VERSION 5.8 ;
BUSBITCHARS "[]" ;
DIVIDERCHAR "/" ;
UNITS
    DATABASE MICRONS 1000 ;
END UNITS

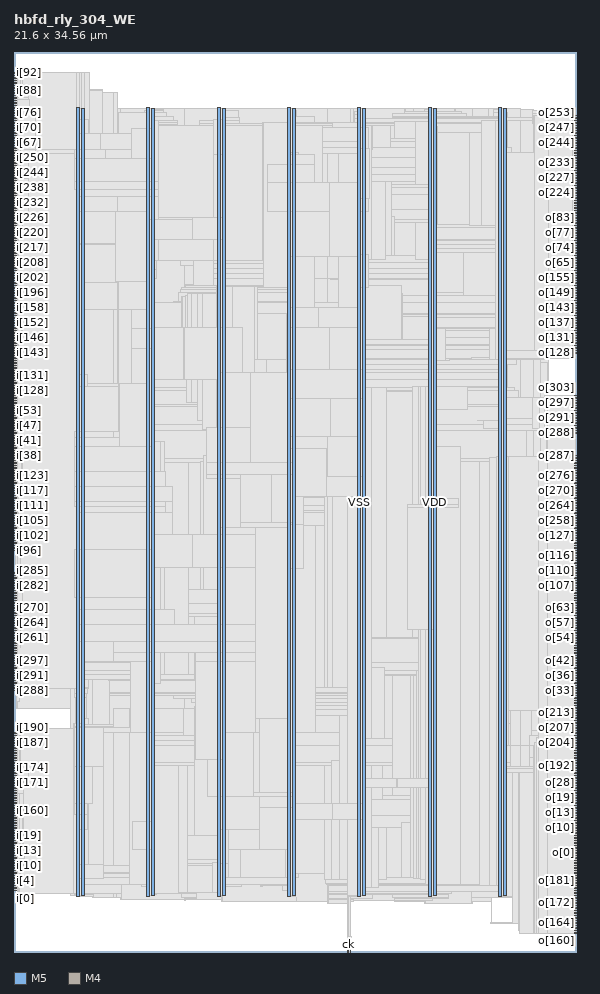
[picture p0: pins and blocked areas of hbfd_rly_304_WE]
MACRO hbfd_rly_304_WE
  FOREIGN hbfd_rly_304_WE 0 0 ;
  CLASS BLOCK ;
  SIZE 21.6 BY 34.56 ;
  PIN ck
    DIRECTION INPUT ;
    USE SIGNAL ;
    PORT
      LAYER M5 ;
        RECT  12.816 0 12.84 0.084 ;
    END
  END ck
  PIN i[0]
    DIRECTION INPUT ;
    USE SIGNAL ;
    PORT
      LAYER M4 ;
        RECT  0 2.352 0.084 2.376 ;
    END
  END i[0]
  PIN i[100]
    DIRECTION INPUT ;
    USE SIGNAL ;
    PORT
      LAYER M4 ;
        RECT  0 15.792 0.084 15.816 ;
    END
  END i[100]
  PIN i[101]
    DIRECTION INPUT ;
    USE SIGNAL ;
    PORT
      LAYER M4 ;
        RECT  0 15.888 0.084 15.912 ;
    END
  END i[101]
  PIN i[102]
    DIRECTION INPUT ;
    USE SIGNAL ;
    PORT
      LAYER M4 ;
        RECT  0 15.984 0.084 16.008 ;
    END
  END i[102]
  PIN i[103]
    DIRECTION INPUT ;
    USE SIGNAL ;
    PORT
      LAYER M4 ;
        RECT  0 16.08 0.084 16.104 ;
    END
  END i[103]
  PIN i[104]
    DIRECTION INPUT ;
    USE SIGNAL ;
    PORT
      LAYER M4 ;
        RECT  0 16.176 0.084 16.2 ;
    END
  END i[104]
  PIN i[105]
    DIRECTION INPUT ;
    USE SIGNAL ;
    PORT
      LAYER M4 ;
        RECT  0 16.272 0.084 16.296 ;
    END
  END i[105]
  PIN i[106]
    DIRECTION INPUT ;
    USE SIGNAL ;
    PORT
      LAYER M4 ;
        RECT  0 16.368 0.084 16.392 ;
    END
  END i[106]
  PIN i[107]
    DIRECTION INPUT ;
    USE SIGNAL ;
    PORT
      LAYER M4 ;
        RECT  0 16.464 0.084 16.488 ;
    END
  END i[107]
  PIN i[108]
    DIRECTION INPUT ;
    USE SIGNAL ;
    PORT
      LAYER M4 ;
        RECT  0 16.56 0.084 16.584 ;
    END
  END i[108]
  PIN i[109]
    DIRECTION INPUT ;
    USE SIGNAL ;
    PORT
      LAYER M4 ;
        RECT  0 16.656 0.084 16.68 ;
    END
  END i[109]
  PIN i[10]
    DIRECTION INPUT ;
    USE SIGNAL ;
    PORT
      LAYER M4 ;
        RECT  0 3.312 0.084 3.336 ;
    END
  END i[10]
  PIN i[110]
    DIRECTION INPUT ;
    USE SIGNAL ;
    PORT
      LAYER M4 ;
        RECT  0 16.752 0.084 16.776 ;
    END
  END i[110]
  PIN i[111]
    DIRECTION INPUT ;
    USE SIGNAL ;
    PORT
      LAYER M4 ;
        RECT  0 16.848 0.084 16.872 ;
    END
  END i[111]
  PIN i[112]
    DIRECTION INPUT ;
    USE SIGNAL ;
    PORT
      LAYER M4 ;
        RECT  0 16.944 0.084 16.968 ;
    END
  END i[112]
  PIN i[113]
    DIRECTION INPUT ;
    USE SIGNAL ;
    PORT
      LAYER M4 ;
        RECT  0 17.04 0.084 17.064 ;
    END
  END i[113]
  PIN i[114]
    DIRECTION INPUT ;
    USE SIGNAL ;
    PORT
      LAYER M4 ;
        RECT  0 17.136 0.084 17.16 ;
    END
  END i[114]
  PIN i[115]
    DIRECTION INPUT ;
    USE SIGNAL ;
    PORT
      LAYER M4 ;
        RECT  0 17.232 0.084 17.256 ;
    END
  END i[115]
  PIN i[116]
    DIRECTION INPUT ;
    USE SIGNAL ;
    PORT
      LAYER M4 ;
        RECT  0 17.328 0.084 17.352 ;
    END
  END i[116]
  PIN i[117]
    DIRECTION INPUT ;
    USE SIGNAL ;
    PORT
      LAYER M4 ;
        RECT  0 17.424 0.084 17.448 ;
    END
  END i[117]
  PIN i[118]
    DIRECTION INPUT ;
    USE SIGNAL ;
    PORT
      LAYER M4 ;
        RECT  0 17.52 0.084 17.544 ;
    END
  END i[118]
  PIN i[119]
    DIRECTION INPUT ;
    USE SIGNAL ;
    PORT
      LAYER M4 ;
        RECT  0 17.616 0.084 17.64 ;
    END
  END i[119]
  PIN i[11]
    DIRECTION INPUT ;
    USE SIGNAL ;
    PORT
      LAYER M4 ;
        RECT  0 3.408 0.084 3.432 ;
    END
  END i[11]
  PIN i[120]
    DIRECTION INPUT ;
    USE SIGNAL ;
    PORT
      LAYER M4 ;
        RECT  0 17.712 0.084 17.736 ;
    END
  END i[120]
  PIN i[121]
    DIRECTION INPUT ;
    USE SIGNAL ;
    PORT
      LAYER M4 ;
        RECT  0 17.808 0.084 17.832 ;
    END
  END i[121]
  PIN i[122]
    DIRECTION INPUT ;
    USE SIGNAL ;
    PORT
      LAYER M4 ;
        RECT  0 17.904 0.084 17.928 ;
    END
  END i[122]
  PIN i[123]
    DIRECTION INPUT ;
    USE SIGNAL ;
    PORT
      LAYER M4 ;
        RECT  0 18 0.084 18.024 ;
    END
  END i[123]
  PIN i[124]
    DIRECTION INPUT ;
    USE SIGNAL ;
    PORT
      LAYER M4 ;
        RECT  0 18.096 0.084 18.12 ;
    END
  END i[124]
  PIN i[125]
    DIRECTION INPUT ;
    USE SIGNAL ;
    PORT
      LAYER M4 ;
        RECT  0 18.192 0.084 18.216 ;
    END
  END i[125]
  PIN i[126]
    DIRECTION INPUT ;
    USE SIGNAL ;
    PORT
      LAYER M4 ;
        RECT  0 18.288 0.084 18.312 ;
    END
  END i[126]
  PIN i[127]
    DIRECTION INPUT ;
    USE SIGNAL ;
    PORT
      LAYER M4 ;
        RECT  0 18.384 0.084 18.408 ;
    END
  END i[127]
  PIN i[128]
    DIRECTION INPUT ;
    USE SIGNAL ;
    PORT
      LAYER M4 ;
        RECT  0 21.552 0.084 21.576 ;
    END
  END i[128]
  PIN i[129]
    DIRECTION INPUT ;
    USE SIGNAL ;
    PORT
      LAYER M4 ;
        RECT  0 21.648 0.084 21.672 ;
    END
  END i[129]
  PIN i[12]
    DIRECTION INPUT ;
    USE SIGNAL ;
    PORT
      LAYER M4 ;
        RECT  0 3.504 0.084 3.528 ;
    END
  END i[12]
  PIN i[130]
    DIRECTION INPUT ;
    USE SIGNAL ;
    PORT
      LAYER M4 ;
        RECT  0 21.744 0.084 21.768 ;
    END
  END i[130]
  PIN i[131]
    DIRECTION INPUT ;
    USE SIGNAL ;
    PORT
      LAYER M4 ;
        RECT  0 21.84 0.084 21.864 ;
    END
  END i[131]
  PIN i[132]
    DIRECTION INPUT ;
    USE SIGNAL ;
    PORT
      LAYER M4 ;
        RECT  0 21.936 0.084 21.96 ;
    END
  END i[132]
  PIN i[133]
    DIRECTION INPUT ;
    USE SIGNAL ;
    PORT
      LAYER M4 ;
        RECT  0 22.032 0.084 22.056 ;
    END
  END i[133]
  PIN i[134]
    DIRECTION INPUT ;
    USE SIGNAL ;
    PORT
      LAYER M4 ;
        RECT  0 22.128 0.084 22.152 ;
    END
  END i[134]
  PIN i[135]
    DIRECTION INPUT ;
    USE SIGNAL ;
    PORT
      LAYER M4 ;
        RECT  0 22.224 0.084 22.248 ;
    END
  END i[135]
  PIN i[136]
    DIRECTION INPUT ;
    USE SIGNAL ;
    PORT
      LAYER M4 ;
        RECT  0 22.32 0.084 22.344 ;
    END
  END i[136]
  PIN i[137]
    DIRECTION INPUT ;
    USE SIGNAL ;
    PORT
      LAYER M4 ;
        RECT  0 22.416 0.084 22.44 ;
    END
  END i[137]
  PIN i[138]
    DIRECTION INPUT ;
    USE SIGNAL ;
    PORT
      LAYER M4 ;
        RECT  0 22.512 0.084 22.536 ;
    END
  END i[138]
  PIN i[139]
    DIRECTION INPUT ;
    USE SIGNAL ;
    PORT
      LAYER M4 ;
        RECT  0 22.608 0.084 22.632 ;
    END
  END i[139]
  PIN i[13]
    DIRECTION INPUT ;
    USE SIGNAL ;
    PORT
      LAYER M4 ;
        RECT  0 3.6 0.084 3.624 ;
    END
  END i[13]
  PIN i[140]
    DIRECTION INPUT ;
    USE SIGNAL ;
    PORT
      LAYER M4 ;
        RECT  0 22.704 0.084 22.728 ;
    END
  END i[140]
  PIN i[141]
    DIRECTION INPUT ;
    USE SIGNAL ;
    PORT
      LAYER M4 ;
        RECT  0 22.8 0.084 22.824 ;
    END
  END i[141]
  PIN i[142]
    DIRECTION INPUT ;
    USE SIGNAL ;
    PORT
      LAYER M4 ;
        RECT  0 22.896 0.084 22.92 ;
    END
  END i[142]
  PIN i[143]
    DIRECTION INPUT ;
    USE SIGNAL ;
    PORT
      LAYER M4 ;
        RECT  0 22.992 0.084 23.016 ;
    END
  END i[143]
  PIN i[144]
    DIRECTION INPUT ;
    USE SIGNAL ;
    PORT
      LAYER M4 ;
        RECT  0 23.088 0.084 23.112 ;
    END
  END i[144]
  PIN i[145]
    DIRECTION INPUT ;
    USE SIGNAL ;
    PORT
      LAYER M4 ;
        RECT  0 23.184 0.084 23.208 ;
    END
  END i[145]
  PIN i[146]
    DIRECTION INPUT ;
    USE SIGNAL ;
    PORT
      LAYER M4 ;
        RECT  0 23.28 0.084 23.304 ;
    END
  END i[146]
  PIN i[147]
    DIRECTION INPUT ;
    USE SIGNAL ;
    PORT
      LAYER M4 ;
        RECT  0 23.376 0.084 23.4 ;
    END
  END i[147]
  PIN i[148]
    DIRECTION INPUT ;
    USE SIGNAL ;
    PORT
      LAYER M4 ;
        RECT  0 23.472 0.084 23.496 ;
    END
  END i[148]
  PIN i[149]
    DIRECTION INPUT ;
    USE SIGNAL ;
    PORT
      LAYER M4 ;
        RECT  0 23.568 0.084 23.592 ;
    END
  END i[149]
  PIN i[14]
    DIRECTION INPUT ;
    USE SIGNAL ;
    PORT
      LAYER M4 ;
        RECT  0 3.696 0.084 3.72 ;
    END
  END i[14]
  PIN i[150]
    DIRECTION INPUT ;
    USE SIGNAL ;
    PORT
      LAYER M4 ;
        RECT  0 23.664 0.084 23.688 ;
    END
  END i[150]
  PIN i[151]
    DIRECTION INPUT ;
    USE SIGNAL ;
    PORT
      LAYER M4 ;
        RECT  0 23.76 0.084 23.784 ;
    END
  END i[151]
  PIN i[152]
    DIRECTION INPUT ;
    USE SIGNAL ;
    PORT
      LAYER M4 ;
        RECT  0 23.856 0.084 23.88 ;
    END
  END i[152]
  PIN i[153]
    DIRECTION INPUT ;
    USE SIGNAL ;
    PORT
      LAYER M4 ;
        RECT  0 23.952 0.084 23.976 ;
    END
  END i[153]
  PIN i[154]
    DIRECTION INPUT ;
    USE SIGNAL ;
    PORT
      LAYER M4 ;
        RECT  0 24.048 0.084 24.072 ;
    END
  END i[154]
  PIN i[155]
    DIRECTION INPUT ;
    USE SIGNAL ;
    PORT
      LAYER M4 ;
        RECT  0 24.144 0.084 24.168 ;
    END
  END i[155]
  PIN i[156]
    DIRECTION INPUT ;
    USE SIGNAL ;
    PORT
      LAYER M4 ;
        RECT  0 24.24 0.084 24.264 ;
    END
  END i[156]
  PIN i[157]
    DIRECTION INPUT ;
    USE SIGNAL ;
    PORT
      LAYER M4 ;
        RECT  0 24.336 0.084 24.36 ;
    END
  END i[157]
  PIN i[158]
    DIRECTION INPUT ;
    USE SIGNAL ;
    PORT
      LAYER M4 ;
        RECT  0 24.432 0.084 24.456 ;
    END
  END i[158]
  PIN i[159]
    DIRECTION INPUT ;
    USE SIGNAL ;
    PORT
      LAYER M4 ;
        RECT  0 24.528 0.084 24.552 ;
    END
  END i[159]
  PIN i[15]
    DIRECTION INPUT ;
    USE SIGNAL ;
    PORT
      LAYER M4 ;
        RECT  0 3.792 0.084 3.816 ;
    END
  END i[15]
  PIN i[160]
    DIRECTION INPUT ;
    USE SIGNAL ;
    PORT
      LAYER M4 ;
        RECT  0 5.424 0.084 5.448 ;
    END
  END i[160]
  PIN i[161]
    DIRECTION INPUT ;
    USE SIGNAL ;
    PORT
      LAYER M4 ;
        RECT  0 5.52 0.084 5.544 ;
    END
  END i[161]
  PIN i[162]
    DIRECTION INPUT ;
    USE SIGNAL ;
    PORT
      LAYER M4 ;
        RECT  0 5.616 0.084 5.64 ;
    END
  END i[162]
  PIN i[163]
    DIRECTION INPUT ;
    USE SIGNAL ;
    PORT
      LAYER M4 ;
        RECT  0 5.712 0.084 5.736 ;
    END
  END i[163]
  PIN i[164]
    DIRECTION INPUT ;
    USE SIGNAL ;
    PORT
      LAYER M4 ;
        RECT  0 5.808 0.084 5.832 ;
    END
  END i[164]
  PIN i[165]
    DIRECTION INPUT ;
    USE SIGNAL ;
    PORT
      LAYER M4 ;
        RECT  0 5.904 0.084 5.928 ;
    END
  END i[165]
  PIN i[166]
    DIRECTION INPUT ;
    USE SIGNAL ;
    PORT
      LAYER M4 ;
        RECT  0 6 0.084 6.024 ;
    END
  END i[166]
  PIN i[167]
    DIRECTION INPUT ;
    USE SIGNAL ;
    PORT
      LAYER M4 ;
        RECT  0 6.096 0.084 6.12 ;
    END
  END i[167]
  PIN i[168]
    DIRECTION INPUT ;
    USE SIGNAL ;
    PORT
      LAYER M4 ;
        RECT  0 6.192 0.084 6.216 ;
    END
  END i[168]
  PIN i[169]
    DIRECTION INPUT ;
    USE SIGNAL ;
    PORT
      LAYER M4 ;
        RECT  0 6.288 0.084 6.312 ;
    END
  END i[169]
  PIN i[16]
    DIRECTION INPUT ;
    USE SIGNAL ;
    PORT
      LAYER M4 ;
        RECT  0 3.888 0.084 3.912 ;
    END
  END i[16]
  PIN i[170]
    DIRECTION INPUT ;
    USE SIGNAL ;
    PORT
      LAYER M4 ;
        RECT  0 6.384 0.084 6.408 ;
    END
  END i[170]
  PIN i[171]
    DIRECTION INPUT ;
    USE SIGNAL ;
    PORT
      LAYER M4 ;
        RECT  0 6.48 0.084 6.504 ;
    END
  END i[171]
  PIN i[172]
    DIRECTION INPUT ;
    USE SIGNAL ;
    PORT
      LAYER M4 ;
        RECT  0 6.576 0.084 6.6 ;
    END
  END i[172]
  PIN i[173]
    DIRECTION INPUT ;
    USE SIGNAL ;
    PORT
      LAYER M4 ;
        RECT  0 6.672 0.084 6.696 ;
    END
  END i[173]
  PIN i[174]
    DIRECTION INPUT ;
    USE SIGNAL ;
    PORT
      LAYER M4 ;
        RECT  0 6.768 0.084 6.792 ;
    END
  END i[174]
  PIN i[175]
    DIRECTION INPUT ;
    USE SIGNAL ;
    PORT
      LAYER M4 ;
        RECT  0 6.864 0.084 6.888 ;
    END
  END i[175]
  PIN i[176]
    DIRECTION INPUT ;
    USE SIGNAL ;
    PORT
      LAYER M4 ;
        RECT  0 6.96 0.084 6.984 ;
    END
  END i[176]
  PIN i[177]
    DIRECTION INPUT ;
    USE SIGNAL ;
    PORT
      LAYER M4 ;
        RECT  0 7.056 0.084 7.08 ;
    END
  END i[177]
  PIN i[178]
    DIRECTION INPUT ;
    USE SIGNAL ;
    PORT
      LAYER M4 ;
        RECT  0 7.152 0.084 7.176 ;
    END
  END i[178]
  PIN i[179]
    DIRECTION INPUT ;
    USE SIGNAL ;
    PORT
      LAYER M4 ;
        RECT  0 7.248 0.084 7.272 ;
    END
  END i[179]
  PIN i[17]
    DIRECTION INPUT ;
    USE SIGNAL ;
    PORT
      LAYER M4 ;
        RECT  0 3.984 0.084 4.008 ;
    END
  END i[17]
  PIN i[180]
    DIRECTION INPUT ;
    USE SIGNAL ;
    PORT
      LAYER M4 ;
        RECT  0 7.344 0.084 7.368 ;
    END
  END i[180]
  PIN i[181]
    DIRECTION INPUT ;
    USE SIGNAL ;
    PORT
      LAYER M4 ;
        RECT  0 7.44 0.084 7.464 ;
    END
  END i[181]
  PIN i[182]
    DIRECTION INPUT ;
    USE SIGNAL ;
    PORT
      LAYER M4 ;
        RECT  0 7.536 0.084 7.56 ;
    END
  END i[182]
  PIN i[183]
    DIRECTION INPUT ;
    USE SIGNAL ;
    PORT
      LAYER M4 ;
        RECT  0 7.632 0.084 7.656 ;
    END
  END i[183]
  PIN i[184]
    DIRECTION INPUT ;
    USE SIGNAL ;
    PORT
      LAYER M4 ;
        RECT  0 7.728 0.084 7.752 ;
    END
  END i[184]
  PIN i[185]
    DIRECTION INPUT ;
    USE SIGNAL ;
    PORT
      LAYER M4 ;
        RECT  0 7.824 0.084 7.848 ;
    END
  END i[185]
  PIN i[186]
    DIRECTION INPUT ;
    USE SIGNAL ;
    PORT
      LAYER M4 ;
        RECT  0 7.92 0.084 7.944 ;
    END
  END i[186]
  PIN i[187]
    DIRECTION INPUT ;
    USE SIGNAL ;
    PORT
      LAYER M4 ;
        RECT  0 8.016 0.084 8.04 ;
    END
  END i[187]
  PIN i[188]
    DIRECTION INPUT ;
    USE SIGNAL ;
    PORT
      LAYER M4 ;
        RECT  0 8.112 0.084 8.136 ;
    END
  END i[188]
  PIN i[189]
    DIRECTION INPUT ;
    USE SIGNAL ;
    PORT
      LAYER M4 ;
        RECT  0 8.208 0.084 8.232 ;
    END
  END i[189]
  PIN i[18]
    DIRECTION INPUT ;
    USE SIGNAL ;
    PORT
      LAYER M4 ;
        RECT  0 4.08 0.084 4.104 ;
    END
  END i[18]
  PIN i[190]
    DIRECTION INPUT ;
    USE SIGNAL ;
    PORT
      LAYER M4 ;
        RECT  0 8.304 0.084 8.328 ;
    END
  END i[190]
  PIN i[191]
    DIRECTION INPUT ;
    USE SIGNAL ;
    PORT
      LAYER M4 ;
        RECT  0 8.4 0.084 8.424 ;
    END
  END i[191]
  PIN i[192]
    DIRECTION INPUT ;
    USE SIGNAL ;
    PORT
      LAYER M4 ;
        RECT  0 24.624 0.084 24.648 ;
    END
  END i[192]
  PIN i[193]
    DIRECTION INPUT ;
    USE SIGNAL ;
    PORT
      LAYER M4 ;
        RECT  0 24.72 0.084 24.744 ;
    END
  END i[193]
  PIN i[194]
    DIRECTION INPUT ;
    USE SIGNAL ;
    PORT
      LAYER M4 ;
        RECT  0 24.816 0.084 24.84 ;
    END
  END i[194]
  PIN i[195]
    DIRECTION INPUT ;
    USE SIGNAL ;
    PORT
      LAYER M4 ;
        RECT  0 24.912 0.084 24.936 ;
    END
  END i[195]
  PIN i[196]
    DIRECTION INPUT ;
    USE SIGNAL ;
    PORT
      LAYER M4 ;
        RECT  0 25.008 0.084 25.032 ;
    END
  END i[196]
  PIN i[197]
    DIRECTION INPUT ;
    USE SIGNAL ;
    PORT
      LAYER M4 ;
        RECT  0 25.104 0.084 25.128 ;
    END
  END i[197]
  PIN i[198]
    DIRECTION INPUT ;
    USE SIGNAL ;
    PORT
      LAYER M4 ;
        RECT  0 25.2 0.084 25.224 ;
    END
  END i[198]
  PIN i[199]
    DIRECTION INPUT ;
    USE SIGNAL ;
    PORT
      LAYER M4 ;
        RECT  0 25.296 0.084 25.32 ;
    END
  END i[199]
  PIN i[19]
    DIRECTION INPUT ;
    USE SIGNAL ;
    PORT
      LAYER M4 ;
        RECT  0 4.176 0.084 4.2 ;
    END
  END i[19]
  PIN i[1]
    DIRECTION INPUT ;
    USE SIGNAL ;
    PORT
      LAYER M4 ;
        RECT  0 2.448 0.084 2.472 ;
    END
  END i[1]
  PIN i[200]
    DIRECTION INPUT ;
    USE SIGNAL ;
    PORT
      LAYER M4 ;
        RECT  0 25.392 0.084 25.416 ;
    END
  END i[200]
  PIN i[201]
    DIRECTION INPUT ;
    USE SIGNAL ;
    PORT
      LAYER M4 ;
        RECT  0 25.488 0.084 25.512 ;
    END
  END i[201]
  PIN i[202]
    DIRECTION INPUT ;
    USE SIGNAL ;
    PORT
      LAYER M4 ;
        RECT  0 25.584 0.084 25.608 ;
    END
  END i[202]
  PIN i[203]
    DIRECTION INPUT ;
    USE SIGNAL ;
    PORT
      LAYER M4 ;
        RECT  0 25.68 0.084 25.704 ;
    END
  END i[203]
  PIN i[204]
    DIRECTION INPUT ;
    USE SIGNAL ;
    PORT
      LAYER M4 ;
        RECT  0 25.776 0.084 25.8 ;
    END
  END i[204]
  PIN i[205]
    DIRECTION INPUT ;
    USE SIGNAL ;
    PORT
      LAYER M4 ;
        RECT  0 25.872 0.084 25.896 ;
    END
  END i[205]
  PIN i[206]
    DIRECTION INPUT ;
    USE SIGNAL ;
    PORT
      LAYER M4 ;
        RECT  0 25.968 0.084 25.992 ;
    END
  END i[206]
  PIN i[207]
    DIRECTION INPUT ;
    USE SIGNAL ;
    PORT
      LAYER M4 ;
        RECT  0 26.064 0.084 26.088 ;
    END
  END i[207]
  PIN i[208]
    DIRECTION INPUT ;
    USE SIGNAL ;
    PORT
      LAYER M4 ;
        RECT  0 26.16 0.084 26.184 ;
    END
  END i[208]
  PIN i[209]
    DIRECTION INPUT ;
    USE SIGNAL ;
    PORT
      LAYER M4 ;
        RECT  0 26.256 0.084 26.28 ;
    END
  END i[209]
  PIN i[20]
    DIRECTION INPUT ;
    USE SIGNAL ;
    PORT
      LAYER M4 ;
        RECT  0 4.272 0.084 4.296 ;
    END
  END i[20]
  PIN i[210]
    DIRECTION INPUT ;
    USE SIGNAL ;
    PORT
      LAYER M4 ;
        RECT  0 26.352 0.084 26.376 ;
    END
  END i[210]
  PIN i[211]
    DIRECTION INPUT ;
    USE SIGNAL ;
    PORT
      LAYER M4 ;
        RECT  0 26.448 0.084 26.472 ;
    END
  END i[211]
  PIN i[212]
    DIRECTION INPUT ;
    USE SIGNAL ;
    PORT
      LAYER M4 ;
        RECT  0 26.544 0.084 26.568 ;
    END
  END i[212]
  PIN i[213]
    DIRECTION INPUT ;
    USE SIGNAL ;
    PORT
      LAYER M4 ;
        RECT  0 26.64 0.084 26.664 ;
    END
  END i[213]
  PIN i[214]
    DIRECTION INPUT ;
    USE SIGNAL ;
    PORT
      LAYER M4 ;
        RECT  0 26.736 0.084 26.76 ;
    END
  END i[214]
  PIN i[215]
    DIRECTION INPUT ;
    USE SIGNAL ;
    PORT
      LAYER M4 ;
        RECT  0 26.832 0.084 26.856 ;
    END
  END i[215]
  PIN i[216]
    DIRECTION INPUT ;
    USE SIGNAL ;
    PORT
      LAYER M4 ;
        RECT  0 26.928 0.084 26.952 ;
    END
  END i[216]
  PIN i[217]
    DIRECTION INPUT ;
    USE SIGNAL ;
    PORT
      LAYER M4 ;
        RECT  0 27.024 0.084 27.048 ;
    END
  END i[217]
  PIN i[218]
    DIRECTION INPUT ;
    USE SIGNAL ;
    PORT
      LAYER M4 ;
        RECT  0 27.12 0.084 27.144 ;
    END
  END i[218]
  PIN i[219]
    DIRECTION INPUT ;
    USE SIGNAL ;
    PORT
      LAYER M4 ;
        RECT  0 27.216 0.084 27.24 ;
    END
  END i[219]
  PIN i[21]
    DIRECTION INPUT ;
    USE SIGNAL ;
    PORT
      LAYER M4 ;
        RECT  0 4.368 0.084 4.392 ;
    END
  END i[21]
  PIN i[220]
    DIRECTION INPUT ;
    USE SIGNAL ;
    PORT
      LAYER M4 ;
        RECT  0 27.312 0.084 27.336 ;
    END
  END i[220]
  PIN i[221]
    DIRECTION INPUT ;
    USE SIGNAL ;
    PORT
      LAYER M4 ;
        RECT  0 27.408 0.084 27.432 ;
    END
  END i[221]
  PIN i[222]
    DIRECTION INPUT ;
    USE SIGNAL ;
    PORT
      LAYER M4 ;
        RECT  0 27.504 0.084 27.528 ;
    END
  END i[222]
  PIN i[223]
    DIRECTION INPUT ;
    USE SIGNAL ;
    PORT
      LAYER M4 ;
        RECT  0 27.6 0.084 27.624 ;
    END
  END i[223]
  PIN i[224]
    DIRECTION INPUT ;
    USE SIGNAL ;
    PORT
      LAYER M4 ;
        RECT  0 27.696 0.084 27.72 ;
    END
  END i[224]
  PIN i[225]
    DIRECTION INPUT ;
    USE SIGNAL ;
    PORT
      LAYER M4 ;
        RECT  0 27.792 0.084 27.816 ;
    END
  END i[225]
  PIN i[226]
    DIRECTION INPUT ;
    USE SIGNAL ;
    PORT
      LAYER M4 ;
        RECT  0 27.888 0.084 27.912 ;
    END
  END i[226]
  PIN i[227]
    DIRECTION INPUT ;
    USE SIGNAL ;
    PORT
      LAYER M4 ;
        RECT  0 27.984 0.084 28.008 ;
    END
  END i[227]
  PIN i[228]
    DIRECTION INPUT ;
    USE SIGNAL ;
    PORT
      LAYER M4 ;
        RECT  0 28.08 0.084 28.104 ;
    END
  END i[228]
  PIN i[229]
    DIRECTION INPUT ;
    USE SIGNAL ;
    PORT
      LAYER M4 ;
        RECT  0 28.176 0.084 28.2 ;
    END
  END i[229]
  PIN i[22]
    DIRECTION INPUT ;
    USE SIGNAL ;
    PORT
      LAYER M4 ;
        RECT  0 4.464 0.084 4.488 ;
    END
  END i[22]
  PIN i[230]
    DIRECTION INPUT ;
    USE SIGNAL ;
    PORT
      LAYER M4 ;
        RECT  0 28.272 0.084 28.296 ;
    END
  END i[230]
  PIN i[231]
    DIRECTION INPUT ;
    USE SIGNAL ;
    PORT
      LAYER M4 ;
        RECT  0 28.368 0.084 28.392 ;
    END
  END i[231]
  PIN i[232]
    DIRECTION INPUT ;
    USE SIGNAL ;
    PORT
      LAYER M4 ;
        RECT  0 28.464 0.084 28.488 ;
    END
  END i[232]
  PIN i[233]
    DIRECTION INPUT ;
    USE SIGNAL ;
    PORT
      LAYER M4 ;
        RECT  0 28.56 0.084 28.584 ;
    END
  END i[233]
  PIN i[234]
    DIRECTION INPUT ;
    USE SIGNAL ;
    PORT
      LAYER M4 ;
        RECT  0 28.656 0.084 28.68 ;
    END
  END i[234]
  PIN i[235]
    DIRECTION INPUT ;
    USE SIGNAL ;
    PORT
      LAYER M4 ;
        RECT  0 28.752 0.084 28.776 ;
    END
  END i[235]
  PIN i[236]
    DIRECTION INPUT ;
    USE SIGNAL ;
    PORT
      LAYER M4 ;
        RECT  0 28.848 0.084 28.872 ;
    END
  END i[236]
  PIN i[237]
    DIRECTION INPUT ;
    USE SIGNAL ;
    PORT
      LAYER M4 ;
        RECT  0 28.944 0.084 28.968 ;
    END
  END i[237]
  PIN i[238]
    DIRECTION INPUT ;
    USE SIGNAL ;
    PORT
      LAYER M4 ;
        RECT  0 29.04 0.084 29.064 ;
    END
  END i[238]
  PIN i[239]
    DIRECTION INPUT ;
    USE SIGNAL ;
    PORT
      LAYER M4 ;
        RECT  0 29.136 0.084 29.16 ;
    END
  END i[239]
  PIN i[23]
    DIRECTION INPUT ;
    USE SIGNAL ;
    PORT
      LAYER M4 ;
        RECT  0 4.56 0.084 4.584 ;
    END
  END i[23]
  PIN i[240]
    DIRECTION INPUT ;
    USE SIGNAL ;
    PORT
      LAYER M4 ;
        RECT  0 29.232 0.084 29.256 ;
    END
  END i[240]
  PIN i[241]
    DIRECTION INPUT ;
    USE SIGNAL ;
    PORT
      LAYER M4 ;
        RECT  0 29.328 0.084 29.352 ;
    END
  END i[241]
  PIN i[242]
    DIRECTION INPUT ;
    USE SIGNAL ;
    PORT
      LAYER M4 ;
        RECT  0 29.424 0.084 29.448 ;
    END
  END i[242]
  PIN i[243]
    DIRECTION INPUT ;
    USE SIGNAL ;
    PORT
      LAYER M4 ;
        RECT  0 29.52 0.084 29.544 ;
    END
  END i[243]
  PIN i[244]
    DIRECTION INPUT ;
    USE SIGNAL ;
    PORT
      LAYER M4 ;
        RECT  0 29.616 0.084 29.64 ;
    END
  END i[244]
  PIN i[245]
    DIRECTION INPUT ;
    USE SIGNAL ;
    PORT
      LAYER M4 ;
        RECT  0 29.712 0.084 29.736 ;
    END
  END i[245]
  PIN i[246]
    DIRECTION INPUT ;
    USE SIGNAL ;
    PORT
      LAYER M4 ;
        RECT  0 29.808 0.084 29.832 ;
    END
  END i[246]
  PIN i[247]
    DIRECTION INPUT ;
    USE SIGNAL ;
    PORT
      LAYER M4 ;
        RECT  0 29.904 0.084 29.928 ;
    END
  END i[247]
  PIN i[248]
    DIRECTION INPUT ;
    USE SIGNAL ;
    PORT
      LAYER M4 ;
        RECT  0 30 0.084 30.024 ;
    END
  END i[248]
  PIN i[249]
    DIRECTION INPUT ;
    USE SIGNAL ;
    PORT
      LAYER M4 ;
        RECT  0 30.096 0.084 30.12 ;
    END
  END i[249]
  PIN i[24]
    DIRECTION INPUT ;
    USE SIGNAL ;
    PORT
      LAYER M4 ;
        RECT  0 4.656 0.084 4.68 ;
    END
  END i[24]
  PIN i[250]
    DIRECTION INPUT ;
    USE SIGNAL ;
    PORT
      LAYER M4 ;
        RECT  0 30.192 0.084 30.216 ;
    END
  END i[250]
  PIN i[251]
    DIRECTION INPUT ;
    USE SIGNAL ;
    PORT
      LAYER M4 ;
        RECT  0 30.288 0.084 30.312 ;
    END
  END i[251]
  PIN i[252]
    DIRECTION INPUT ;
    USE SIGNAL ;
    PORT
      LAYER M4 ;
        RECT  0 30.384 0.084 30.408 ;
    END
  END i[252]
  PIN i[253]
    DIRECTION INPUT ;
    USE SIGNAL ;
    PORT
      LAYER M4 ;
        RECT  0 30.48 0.084 30.504 ;
    END
  END i[253]
  PIN i[254]
    DIRECTION INPUT ;
    USE SIGNAL ;
    PORT
      LAYER M4 ;
        RECT  0 30.576 0.084 30.6 ;
    END
  END i[254]
  PIN i[255]
    DIRECTION INPUT ;
    USE SIGNAL ;
    PORT
      LAYER M4 ;
        RECT  0 30.672 0.084 30.696 ;
    END
  END i[255]
  PIN i[256]
    DIRECTION INPUT ;
    USE SIGNAL ;
    PORT
      LAYER M4 ;
        RECT  0 11.568 0.084 11.592 ;
    END
  END i[256]
  PIN i[257]
    DIRECTION INPUT ;
    USE SIGNAL ;
    PORT
      LAYER M4 ;
        RECT  0 11.664 0.084 11.688 ;
    END
  END i[257]
  PIN i[258]
    DIRECTION INPUT ;
    USE SIGNAL ;
    PORT
      LAYER M4 ;
        RECT  0 11.76 0.084 11.784 ;
    END
  END i[258]
  PIN i[259]
    DIRECTION INPUT ;
    USE SIGNAL ;
    PORT
      LAYER M4 ;
        RECT  0 11.856 0.084 11.88 ;
    END
  END i[259]
  PIN i[25]
    DIRECTION INPUT ;
    USE SIGNAL ;
    PORT
      LAYER M4 ;
        RECT  0 4.752 0.084 4.776 ;
    END
  END i[25]
  PIN i[260]
    DIRECTION INPUT ;
    USE SIGNAL ;
    PORT
      LAYER M4 ;
        RECT  0 11.952 0.084 11.976 ;
    END
  END i[260]
  PIN i[261]
    DIRECTION INPUT ;
    USE SIGNAL ;
    PORT
      LAYER M4 ;
        RECT  0 12.048 0.084 12.072 ;
    END
  END i[261]
  PIN i[262]
    DIRECTION INPUT ;
    USE SIGNAL ;
    PORT
      LAYER M4 ;
        RECT  0 12.144 0.084 12.168 ;
    END
  END i[262]
  PIN i[263]
    DIRECTION INPUT ;
    USE SIGNAL ;
    PORT
      LAYER M4 ;
        RECT  0 12.24 0.084 12.264 ;
    END
  END i[263]
  PIN i[264]
    DIRECTION INPUT ;
    USE SIGNAL ;
    PORT
      LAYER M4 ;
        RECT  0 12.336 0.084 12.36 ;
    END
  END i[264]
  PIN i[265]
    DIRECTION INPUT ;
    USE SIGNAL ;
    PORT
      LAYER M4 ;
        RECT  0 12.432 0.084 12.456 ;
    END
  END i[265]
  PIN i[266]
    DIRECTION INPUT ;
    USE SIGNAL ;
    PORT
      LAYER M4 ;
        RECT  0 12.528 0.084 12.552 ;
    END
  END i[266]
  PIN i[267]
    DIRECTION INPUT ;
    USE SIGNAL ;
    PORT
      LAYER M4 ;
        RECT  0 12.624 0.084 12.648 ;
    END
  END i[267]
  PIN i[268]
    DIRECTION INPUT ;
    USE SIGNAL ;
    PORT
      LAYER M4 ;
        RECT  0 12.72 0.084 12.744 ;
    END
  END i[268]
  PIN i[269]
    DIRECTION INPUT ;
    USE SIGNAL ;
    PORT
      LAYER M4 ;
        RECT  0 12.816 0.084 12.84 ;
    END
  END i[269]
  PIN i[26]
    DIRECTION INPUT ;
    USE SIGNAL ;
    PORT
      LAYER M4 ;
        RECT  0 4.848 0.084 4.872 ;
    END
  END i[26]
  PIN i[270]
    DIRECTION INPUT ;
    USE SIGNAL ;
    PORT
      LAYER M4 ;
        RECT  0 12.912 0.084 12.936 ;
    END
  END i[270]
  PIN i[271]
    DIRECTION INPUT ;
    USE SIGNAL ;
    PORT
      LAYER M4 ;
        RECT  0 13.008 0.084 13.032 ;
    END
  END i[271]
  PIN i[272]
    DIRECTION INPUT ;
    USE SIGNAL ;
    PORT
      LAYER M4 ;
        RECT  0 13.104 0.084 13.128 ;
    END
  END i[272]
  PIN i[273]
    DIRECTION INPUT ;
    USE SIGNAL ;
    PORT
      LAYER M4 ;
        RECT  0 13.2 0.084 13.224 ;
    END
  END i[273]
  PIN i[274]
    DIRECTION INPUT ;
    USE SIGNAL ;
    PORT
      LAYER M4 ;
        RECT  0 13.296 0.084 13.32 ;
    END
  END i[274]
  PIN i[275]
    DIRECTION INPUT ;
    USE SIGNAL ;
    PORT
      LAYER M4 ;
        RECT  0 13.392 0.084 13.416 ;
    END
  END i[275]
  PIN i[276]
    DIRECTION INPUT ;
    USE SIGNAL ;
    PORT
      LAYER M4 ;
        RECT  0 13.488 0.084 13.512 ;
    END
  END i[276]
  PIN i[277]
    DIRECTION INPUT ;
    USE SIGNAL ;
    PORT
      LAYER M4 ;
        RECT  0 13.584 0.084 13.608 ;
    END
  END i[277]
  PIN i[278]
    DIRECTION INPUT ;
    USE SIGNAL ;
    PORT
      LAYER M4 ;
        RECT  0 13.68 0.084 13.704 ;
    END
  END i[278]
  PIN i[279]
    DIRECTION INPUT ;
    USE SIGNAL ;
    PORT
      LAYER M4 ;
        RECT  0 13.776 0.084 13.8 ;
    END
  END i[279]
  PIN i[27]
    DIRECTION INPUT ;
    USE SIGNAL ;
    PORT
      LAYER M4 ;
        RECT  0 4.944 0.084 4.968 ;
    END
  END i[27]
  PIN i[280]
    DIRECTION INPUT ;
    USE SIGNAL ;
    PORT
      LAYER M4 ;
        RECT  0 13.872 0.084 13.896 ;
    END
  END i[280]
  PIN i[281]
    DIRECTION INPUT ;
    USE SIGNAL ;
    PORT
      LAYER M4 ;
        RECT  0 13.968 0.084 13.992 ;
    END
  END i[281]
  PIN i[282]
    DIRECTION INPUT ;
    USE SIGNAL ;
    PORT
      LAYER M4 ;
        RECT  0 14.064 0.084 14.088 ;
    END
  END i[282]
  PIN i[283]
    DIRECTION INPUT ;
    USE SIGNAL ;
    PORT
      LAYER M4 ;
        RECT  0 14.16 0.084 14.184 ;
    END
  END i[283]
  PIN i[284]
    DIRECTION INPUT ;
    USE SIGNAL ;
    PORT
      LAYER M4 ;
        RECT  0 14.256 0.084 14.28 ;
    END
  END i[284]
  PIN i[285]
    DIRECTION INPUT ;
    USE SIGNAL ;
    PORT
      LAYER M4 ;
        RECT  0 14.352 0.084 14.376 ;
    END
  END i[285]
  PIN i[286]
    DIRECTION INPUT ;
    USE SIGNAL ;
    PORT
      LAYER M4 ;
        RECT  0 14.448 0.084 14.472 ;
    END
  END i[286]
  PIN i[287]
    DIRECTION INPUT ;
    USE SIGNAL ;
    PORT
      LAYER M4 ;
        RECT  0 14.544 0.084 14.568 ;
    END
  END i[287]
  PIN i[288]
    DIRECTION INPUT ;
    USE SIGNAL ;
    PORT
      LAYER M4 ;
        RECT  0 10.032 0.084 10.056 ;
    END
  END i[288]
  PIN i[289]
    DIRECTION INPUT ;
    USE SIGNAL ;
    PORT
      LAYER M4 ;
        RECT  0 10.128 0.084 10.152 ;
    END
  END i[289]
  PIN i[28]
    DIRECTION INPUT ;
    USE SIGNAL ;
    PORT
      LAYER M4 ;
        RECT  0 5.04 0.084 5.064 ;
    END
  END i[28]
  PIN i[290]
    DIRECTION INPUT ;
    USE SIGNAL ;
    PORT
      LAYER M4 ;
        RECT  0 10.224 0.084 10.248 ;
    END
  END i[290]
  PIN i[291]
    DIRECTION INPUT ;
    USE SIGNAL ;
    PORT
      LAYER M4 ;
        RECT  0 10.32 0.084 10.344 ;
    END
  END i[291]
  PIN i[292]
    DIRECTION INPUT ;
    USE SIGNAL ;
    PORT
      LAYER M4 ;
        RECT  0 10.416 0.084 10.44 ;
    END
  END i[292]
  PIN i[293]
    DIRECTION INPUT ;
    USE SIGNAL ;
    PORT
      LAYER M4 ;
        RECT  0 10.512 0.084 10.536 ;
    END
  END i[293]
  PIN i[294]
    DIRECTION INPUT ;
    USE SIGNAL ;
    PORT
      LAYER M4 ;
        RECT  0 10.608 0.084 10.632 ;
    END
  END i[294]
  PIN i[295]
    DIRECTION INPUT ;
    USE SIGNAL ;
    PORT
      LAYER M4 ;
        RECT  0 10.704 0.084 10.728 ;
    END
  END i[295]
  PIN i[296]
    DIRECTION INPUT ;
    USE SIGNAL ;
    PORT
      LAYER M4 ;
        RECT  0 10.8 0.084 10.824 ;
    END
  END i[296]
  PIN i[297]
    DIRECTION INPUT ;
    USE SIGNAL ;
    PORT
      LAYER M4 ;
        RECT  0 10.896 0.084 10.92 ;
    END
  END i[297]
  PIN i[298]
    DIRECTION INPUT ;
    USE SIGNAL ;
    PORT
      LAYER M4 ;
        RECT  0 10.992 0.084 11.016 ;
    END
  END i[298]
  PIN i[299]
    DIRECTION INPUT ;
    USE SIGNAL ;
    PORT
      LAYER M4 ;
        RECT  0 11.088 0.084 11.112 ;
    END
  END i[299]
  PIN i[29]
    DIRECTION INPUT ;
    USE SIGNAL ;
    PORT
      LAYER M4 ;
        RECT  0 5.136 0.084 5.16 ;
    END
  END i[29]
  PIN i[2]
    DIRECTION INPUT ;
    USE SIGNAL ;
    PORT
      LAYER M4 ;
        RECT  0 2.544 0.084 2.568 ;
    END
  END i[2]
  PIN i[300]
    DIRECTION INPUT ;
    USE SIGNAL ;
    PORT
      LAYER M4 ;
        RECT  0 11.184 0.084 11.208 ;
    END
  END i[300]
  PIN i[301]
    DIRECTION INPUT ;
    USE SIGNAL ;
    PORT
      LAYER M4 ;
        RECT  0 11.28 0.084 11.304 ;
    END
  END i[301]
  PIN i[302]
    DIRECTION INPUT ;
    USE SIGNAL ;
    PORT
      LAYER M4 ;
        RECT  0 11.376 0.084 11.4 ;
    END
  END i[302]
  PIN i[303]
    DIRECTION INPUT ;
    USE SIGNAL ;
    PORT
      LAYER M4 ;
        RECT  0 11.472 0.084 11.496 ;
    END
  END i[303]
  PIN i[30]
    DIRECTION INPUT ;
    USE SIGNAL ;
    PORT
      LAYER M4 ;
        RECT  0 5.232 0.084 5.256 ;
    END
  END i[30]
  PIN i[31]
    DIRECTION INPUT ;
    USE SIGNAL ;
    PORT
      LAYER M4 ;
        RECT  0 5.328 0.084 5.352 ;
    END
  END i[31]
  PIN i[32]
    DIRECTION INPUT ;
    USE SIGNAL ;
    PORT
      LAYER M4 ;
        RECT  0 18.48 0.084 18.504 ;
    END
  END i[32]
  PIN i[33]
    DIRECTION INPUT ;
    USE SIGNAL ;
    PORT
      LAYER M4 ;
        RECT  0 18.576 0.084 18.6 ;
    END
  END i[33]
  PIN i[34]
    DIRECTION INPUT ;
    USE SIGNAL ;
    PORT
      LAYER M4 ;
        RECT  0 18.672 0.084 18.696 ;
    END
  END i[34]
  PIN i[35]
    DIRECTION INPUT ;
    USE SIGNAL ;
    PORT
      LAYER M4 ;
        RECT  0 18.768 0.084 18.792 ;
    END
  END i[35]
  PIN i[36]
    DIRECTION INPUT ;
    USE SIGNAL ;
    PORT
      LAYER M4 ;
        RECT  0 18.864 0.084 18.888 ;
    END
  END i[36]
  PIN i[37]
    DIRECTION INPUT ;
    USE SIGNAL ;
    PORT
      LAYER M4 ;
        RECT  0 18.96 0.084 18.984 ;
    END
  END i[37]
  PIN i[38]
    DIRECTION INPUT ;
    USE SIGNAL ;
    PORT
      LAYER M4 ;
        RECT  0 19.056 0.084 19.08 ;
    END
  END i[38]
  PIN i[39]
    DIRECTION INPUT ;
    USE SIGNAL ;
    PORT
      LAYER M4 ;
        RECT  0 19.152 0.084 19.176 ;
    END
  END i[39]
  PIN i[3]
    DIRECTION INPUT ;
    USE SIGNAL ;
    PORT
      LAYER M4 ;
        RECT  0 2.64 0.084 2.664 ;
    END
  END i[3]
  PIN i[40]
    DIRECTION INPUT ;
    USE SIGNAL ;
    PORT
      LAYER M4 ;
        RECT  0 19.248 0.084 19.272 ;
    END
  END i[40]
  PIN i[41]
    DIRECTION INPUT ;
    USE SIGNAL ;
    PORT
      LAYER M4 ;
        RECT  0 19.344 0.084 19.368 ;
    END
  END i[41]
  PIN i[42]
    DIRECTION INPUT ;
    USE SIGNAL ;
    PORT
      LAYER M4 ;
        RECT  0 19.44 0.084 19.464 ;
    END
  END i[42]
  PIN i[43]
    DIRECTION INPUT ;
    USE SIGNAL ;
    PORT
      LAYER M4 ;
        RECT  0 19.536 0.084 19.56 ;
    END
  END i[43]
  PIN i[44]
    DIRECTION INPUT ;
    USE SIGNAL ;
    PORT
      LAYER M4 ;
        RECT  0 19.632 0.084 19.656 ;
    END
  END i[44]
  PIN i[45]
    DIRECTION INPUT ;
    USE SIGNAL ;
    PORT
      LAYER M4 ;
        RECT  0 19.728 0.084 19.752 ;
    END
  END i[45]
  PIN i[46]
    DIRECTION INPUT ;
    USE SIGNAL ;
    PORT
      LAYER M4 ;
        RECT  0 19.824 0.084 19.848 ;
    END
  END i[46]
  PIN i[47]
    DIRECTION INPUT ;
    USE SIGNAL ;
    PORT
      LAYER M4 ;
        RECT  0 19.92 0.084 19.944 ;
    END
  END i[47]
  PIN i[48]
    DIRECTION INPUT ;
    USE SIGNAL ;
    PORT
      LAYER M4 ;
        RECT  0 20.016 0.084 20.04 ;
    END
  END i[48]
  PIN i[49]
    DIRECTION INPUT ;
    USE SIGNAL ;
    PORT
      LAYER M4 ;
        RECT  0 20.112 0.084 20.136 ;
    END
  END i[49]
  PIN i[4]
    DIRECTION INPUT ;
    USE SIGNAL ;
    PORT
      LAYER M4 ;
        RECT  0 2.736 0.084 2.76 ;
    END
  END i[4]
  PIN i[50]
    DIRECTION INPUT ;
    USE SIGNAL ;
    PORT
      LAYER M4 ;
        RECT  0 20.208 0.084 20.232 ;
    END
  END i[50]
  PIN i[51]
    DIRECTION INPUT ;
    USE SIGNAL ;
    PORT
      LAYER M4 ;
        RECT  0 20.304 0.084 20.328 ;
    END
  END i[51]
  PIN i[52]
    DIRECTION INPUT ;
    USE SIGNAL ;
    PORT
      LAYER M4 ;
        RECT  0 20.4 0.084 20.424 ;
    END
  END i[52]
  PIN i[53]
    DIRECTION INPUT ;
    USE SIGNAL ;
    PORT
      LAYER M4 ;
        RECT  0 20.496 0.084 20.52 ;
    END
  END i[53]
  PIN i[54]
    DIRECTION INPUT ;
    USE SIGNAL ;
    PORT
      LAYER M4 ;
        RECT  0 20.592 0.084 20.616 ;
    END
  END i[54]
  PIN i[55]
    DIRECTION INPUT ;
    USE SIGNAL ;
    PORT
      LAYER M4 ;
        RECT  0 20.688 0.084 20.712 ;
    END
  END i[55]
  PIN i[56]
    DIRECTION INPUT ;
    USE SIGNAL ;
    PORT
      LAYER M4 ;
        RECT  0 20.784 0.084 20.808 ;
    END
  END i[56]
  PIN i[57]
    DIRECTION INPUT ;
    USE SIGNAL ;
    PORT
      LAYER M4 ;
        RECT  0 20.88 0.084 20.904 ;
    END
  END i[57]
  PIN i[58]
    DIRECTION INPUT ;
    USE SIGNAL ;
    PORT
      LAYER M4 ;
        RECT  0 20.976 0.084 21 ;
    END
  END i[58]
  PIN i[59]
    DIRECTION INPUT ;
    USE SIGNAL ;
    PORT
      LAYER M4 ;
        RECT  0 21.072 0.084 21.096 ;
    END
  END i[59]
  PIN i[5]
    DIRECTION INPUT ;
    USE SIGNAL ;
    PORT
      LAYER M4 ;
        RECT  0 2.832 0.084 2.856 ;
    END
  END i[5]
  PIN i[60]
    DIRECTION INPUT ;
    USE SIGNAL ;
    PORT
      LAYER M4 ;
        RECT  0 21.168 0.084 21.192 ;
    END
  END i[60]
  PIN i[61]
    DIRECTION INPUT ;
    USE SIGNAL ;
    PORT
      LAYER M4 ;
        RECT  0 21.264 0.084 21.288 ;
    END
  END i[61]
  PIN i[62]
    DIRECTION INPUT ;
    USE SIGNAL ;
    PORT
      LAYER M4 ;
        RECT  0 21.36 0.084 21.384 ;
    END
  END i[62]
  PIN i[63]
    DIRECTION INPUT ;
    USE SIGNAL ;
    PORT
      LAYER M4 ;
        RECT  0 21.456 0.084 21.48 ;
    END
  END i[63]
  PIN i[64]
    DIRECTION INPUT ;
    USE SIGNAL ;
    PORT
      LAYER M4 ;
        RECT  0 30.768 0.084 30.792 ;
    END
  END i[64]
  PIN i[65]
    DIRECTION INPUT ;
    USE SIGNAL ;
    PORT
      LAYER M4 ;
        RECT  0 30.864 0.084 30.888 ;
    END
  END i[65]
  PIN i[66]
    DIRECTION INPUT ;
    USE SIGNAL ;
    PORT
      LAYER M4 ;
        RECT  0 30.96 0.084 30.984 ;
    END
  END i[66]
  PIN i[67]
    DIRECTION INPUT ;
    USE SIGNAL ;
    PORT
      LAYER M4 ;
        RECT  0 31.056 0.084 31.08 ;
    END
  END i[67]
  PIN i[68]
    DIRECTION INPUT ;
    USE SIGNAL ;
    PORT
      LAYER M4 ;
        RECT  0 31.152 0.084 31.176 ;
    END
  END i[68]
  PIN i[69]
    DIRECTION INPUT ;
    USE SIGNAL ;
    PORT
      LAYER M4 ;
        RECT  0 31.248 0.084 31.272 ;
    END
  END i[69]
  PIN i[6]
    DIRECTION INPUT ;
    USE SIGNAL ;
    PORT
      LAYER M4 ;
        RECT  0 2.928 0.084 2.952 ;
    END
  END i[6]
  PIN i[70]
    DIRECTION INPUT ;
    USE SIGNAL ;
    PORT
      LAYER M4 ;
        RECT  0 31.344 0.084 31.368 ;
    END
  END i[70]
  PIN i[71]
    DIRECTION INPUT ;
    USE SIGNAL ;
    PORT
      LAYER M4 ;
        RECT  0 31.44 0.084 31.464 ;
    END
  END i[71]
  PIN i[72]
    DIRECTION INPUT ;
    USE SIGNAL ;
    PORT
      LAYER M4 ;
        RECT  0 31.536 0.084 31.56 ;
    END
  END i[72]
  PIN i[73]
    DIRECTION INPUT ;
    USE SIGNAL ;
    PORT
      LAYER M4 ;
        RECT  0 31.632 0.084 31.656 ;
    END
  END i[73]
  PIN i[74]
    DIRECTION INPUT ;
    USE SIGNAL ;
    PORT
      LAYER M4 ;
        RECT  0 31.728 0.084 31.752 ;
    END
  END i[74]
  PIN i[75]
    DIRECTION INPUT ;
    USE SIGNAL ;
    PORT
      LAYER M4 ;
        RECT  0 31.824 0.084 31.848 ;
    END
  END i[75]
  PIN i[76]
    DIRECTION INPUT ;
    USE SIGNAL ;
    PORT
      LAYER M4 ;
        RECT  0 31.92 0.084 31.944 ;
    END
  END i[76]
  PIN i[77]
    DIRECTION INPUT ;
    USE SIGNAL ;
    PORT
      LAYER M4 ;
        RECT  0 32.016 0.084 32.04 ;
    END
  END i[77]
  PIN i[78]
    DIRECTION INPUT ;
    USE SIGNAL ;
    PORT
      LAYER M4 ;
        RECT  0 32.112 0.084 32.136 ;
    END
  END i[78]
  PIN i[79]
    DIRECTION INPUT ;
    USE SIGNAL ;
    PORT
      LAYER M4 ;
        RECT  0 32.208 0.084 32.232 ;
    END
  END i[79]
  PIN i[7]
    DIRECTION INPUT ;
    USE SIGNAL ;
    PORT
      LAYER M4 ;
        RECT  0 3.024 0.084 3.048 ;
    END
  END i[7]
  PIN i[80]
    DIRECTION INPUT ;
    USE SIGNAL ;
    PORT
      LAYER M4 ;
        RECT  0 32.304 0.084 32.328 ;
    END
  END i[80]
  PIN i[81]
    DIRECTION INPUT ;
    USE SIGNAL ;
    PORT
      LAYER M4 ;
        RECT  0 32.4 0.084 32.424 ;
    END
  END i[81]
  PIN i[82]
    DIRECTION INPUT ;
    USE SIGNAL ;
    PORT
      LAYER M4 ;
        RECT  0 32.496 0.084 32.52 ;
    END
  END i[82]
  PIN i[83]
    DIRECTION INPUT ;
    USE SIGNAL ;
    PORT
      LAYER M4 ;
        RECT  0 32.592 0.084 32.616 ;
    END
  END i[83]
  PIN i[84]
    DIRECTION INPUT ;
    USE SIGNAL ;
    PORT
      LAYER M4 ;
        RECT  0 32.688 0.084 32.712 ;
    END
  END i[84]
  PIN i[85]
    DIRECTION INPUT ;
    USE SIGNAL ;
    PORT
      LAYER M4 ;
        RECT  0 32.784 0.084 32.808 ;
    END
  END i[85]
  PIN i[86]
    DIRECTION INPUT ;
    USE SIGNAL ;
    PORT
      LAYER M4 ;
        RECT  0 32.88 0.084 32.904 ;
    END
  END i[86]
  PIN i[87]
    DIRECTION INPUT ;
    USE SIGNAL ;
    PORT
      LAYER M4 ;
        RECT  0 32.976 0.084 33 ;
    END
  END i[87]
  PIN i[88]
    DIRECTION INPUT ;
    USE SIGNAL ;
    PORT
      LAYER M4 ;
        RECT  0 33.072 0.084 33.096 ;
    END
  END i[88]
  PIN i[89]
    DIRECTION INPUT ;
    USE SIGNAL ;
    PORT
      LAYER M4 ;
        RECT  0 33.168 0.084 33.192 ;
    END
  END i[89]
  PIN i[8]
    DIRECTION INPUT ;
    USE SIGNAL ;
    PORT
      LAYER M4 ;
        RECT  0 3.12 0.084 3.144 ;
    END
  END i[8]
  PIN i[90]
    DIRECTION INPUT ;
    USE SIGNAL ;
    PORT
      LAYER M4 ;
        RECT  0 33.264 0.084 33.288 ;
    END
  END i[90]
  PIN i[91]
    DIRECTION INPUT ;
    USE SIGNAL ;
    PORT
      LAYER M4 ;
        RECT  0 33.36 0.084 33.384 ;
    END
  END i[91]
  PIN i[92]
    DIRECTION INPUT ;
    USE SIGNAL ;
    PORT
      LAYER M4 ;
        RECT  0 33.456 0.084 33.48 ;
    END
  END i[92]
  PIN i[93]
    DIRECTION INPUT ;
    USE SIGNAL ;
    PORT
      LAYER M4 ;
        RECT  0 33.552 0.084 33.576 ;
    END
  END i[93]
  PIN i[94]
    DIRECTION INPUT ;
    USE SIGNAL ;
    PORT
      LAYER M4 ;
        RECT  0 33.648 0.084 33.672 ;
    END
  END i[94]
  PIN i[95]
    DIRECTION INPUT ;
    USE SIGNAL ;
    PORT
      LAYER M4 ;
        RECT  0 33.744 0.084 33.768 ;
    END
  END i[95]
  PIN i[96]
    DIRECTION INPUT ;
    USE SIGNAL ;
    PORT
      LAYER M4 ;
        RECT  0 15.408 0.084 15.432 ;
    END
  END i[96]
  PIN i[97]
    DIRECTION INPUT ;
    USE SIGNAL ;
    PORT
      LAYER M4 ;
        RECT  0 15.504 0.084 15.528 ;
    END
  END i[97]
  PIN i[98]
    DIRECTION INPUT ;
    USE SIGNAL ;
    PORT
      LAYER M4 ;
        RECT  0 15.6 0.084 15.624 ;
    END
  END i[98]
  PIN i[99]
    DIRECTION INPUT ;
    USE SIGNAL ;
    PORT
      LAYER M4 ;
        RECT  0 15.696 0.084 15.72 ;
    END
  END i[99]
  PIN i[9]
    DIRECTION INPUT ;
    USE SIGNAL ;
    PORT
      LAYER M4 ;
        RECT  0 3.216 0.084 3.24 ;
    END
  END i[9]
  PIN o[0]
    DIRECTION OUTPUT ;
    USE SIGNAL ;
    PORT
      LAYER M4 ;
        RECT  21.516 3.792 21.6 3.816 ;
    END
  END o[0]
  PIN o[100]
    DIRECTION OUTPUT ;
    USE SIGNAL ;
    PORT
      LAYER M4 ;
        RECT  21.516 13.392 21.6 13.416 ;
    END
  END o[100]
  PIN o[101]
    DIRECTION OUTPUT ;
    USE SIGNAL ;
    PORT
      LAYER M4 ;
        RECT  21.516 13.488 21.6 13.512 ;
    END
  END o[101]
  PIN o[102]
    DIRECTION OUTPUT ;
    USE SIGNAL ;
    PORT
      LAYER M4 ;
        RECT  21.516 13.584 21.6 13.608 ;
    END
  END o[102]
  PIN o[103]
    DIRECTION OUTPUT ;
    USE SIGNAL ;
    PORT
      LAYER M4 ;
        RECT  21.516 13.68 21.6 13.704 ;
    END
  END o[103]
  PIN o[104]
    DIRECTION OUTPUT ;
    USE SIGNAL ;
    PORT
      LAYER M4 ;
        RECT  21.516 13.776 21.6 13.8 ;
    END
  END o[104]
  PIN o[105]
    DIRECTION OUTPUT ;
    USE SIGNAL ;
    PORT
      LAYER M4 ;
        RECT  21.516 13.872 21.6 13.896 ;
    END
  END o[105]
  PIN o[106]
    DIRECTION OUTPUT ;
    USE SIGNAL ;
    PORT
      LAYER M4 ;
        RECT  21.516 13.968 21.6 13.992 ;
    END
  END o[106]
  PIN o[107]
    DIRECTION OUTPUT ;
    USE SIGNAL ;
    PORT
      LAYER M4 ;
        RECT  21.516 14.064 21.6 14.088 ;
    END
  END o[107]
  PIN o[108]
    DIRECTION OUTPUT ;
    USE SIGNAL ;
    PORT
      LAYER M4 ;
        RECT  21.516 14.16 21.6 14.184 ;
    END
  END o[108]
  PIN o[109]
    DIRECTION OUTPUT ;
    USE SIGNAL ;
    PORT
      LAYER M4 ;
        RECT  21.516 14.256 21.6 14.28 ;
    END
  END o[109]
  PIN o[10]
    DIRECTION OUTPUT ;
    USE SIGNAL ;
    PORT
      LAYER M4 ;
        RECT  21.516 4.752 21.6 4.776 ;
    END
  END o[10]
  PIN o[110]
    DIRECTION OUTPUT ;
    USE SIGNAL ;
    PORT
      LAYER M4 ;
        RECT  21.516 14.352 21.6 14.376 ;
    END
  END o[110]
  PIN o[111]
    DIRECTION OUTPUT ;
    USE SIGNAL ;
    PORT
      LAYER M4 ;
        RECT  21.516 14.448 21.6 14.472 ;
    END
  END o[111]
  PIN o[112]
    DIRECTION OUTPUT ;
    USE SIGNAL ;
    PORT
      LAYER M4 ;
        RECT  21.516 14.544 21.6 14.568 ;
    END
  END o[112]
  PIN o[113]
    DIRECTION OUTPUT ;
    USE SIGNAL ;
    PORT
      LAYER M4 ;
        RECT  21.516 14.64 21.6 14.664 ;
    END
  END o[113]
  PIN o[114]
    DIRECTION OUTPUT ;
    USE SIGNAL ;
    PORT
      LAYER M4 ;
        RECT  21.516 14.736 21.6 14.76 ;
    END
  END o[114]
  PIN o[115]
    DIRECTION OUTPUT ;
    USE SIGNAL ;
    PORT
      LAYER M4 ;
        RECT  21.516 14.832 21.6 14.856 ;
    END
  END o[115]
  PIN o[116]
    DIRECTION OUTPUT ;
    USE SIGNAL ;
    PORT
      LAYER M4 ;
        RECT  21.516 14.928 21.6 14.952 ;
    END
  END o[116]
  PIN o[117]
    DIRECTION OUTPUT ;
    USE SIGNAL ;
    PORT
      LAYER M4 ;
        RECT  21.516 15.024 21.6 15.048 ;
    END
  END o[117]
  PIN o[118]
    DIRECTION OUTPUT ;
    USE SIGNAL ;
    PORT
      LAYER M4 ;
        RECT  21.516 15.12 21.6 15.144 ;
    END
  END o[118]
  PIN o[119]
    DIRECTION OUTPUT ;
    USE SIGNAL ;
    PORT
      LAYER M4 ;
        RECT  21.516 15.216 21.6 15.24 ;
    END
  END o[119]
  PIN o[11]
    DIRECTION OUTPUT ;
    USE SIGNAL ;
    PORT
      LAYER M4 ;
        RECT  21.516 4.848 21.6 4.872 ;
    END
  END o[11]
  PIN o[120]
    DIRECTION OUTPUT ;
    USE SIGNAL ;
    PORT
      LAYER M4 ;
        RECT  21.516 15.312 21.6 15.336 ;
    END
  END o[120]
  PIN o[121]
    DIRECTION OUTPUT ;
    USE SIGNAL ;
    PORT
      LAYER M4 ;
        RECT  21.516 15.408 21.6 15.432 ;
    END
  END o[121]
  PIN o[122]
    DIRECTION OUTPUT ;
    USE SIGNAL ;
    PORT
      LAYER M4 ;
        RECT  21.516 15.504 21.6 15.528 ;
    END
  END o[122]
  PIN o[123]
    DIRECTION OUTPUT ;
    USE SIGNAL ;
    PORT
      LAYER M4 ;
        RECT  21.516 15.6 21.6 15.624 ;
    END
  END o[123]
  PIN o[124]
    DIRECTION OUTPUT ;
    USE SIGNAL ;
    PORT
      LAYER M4 ;
        RECT  21.516 15.696 21.6 15.72 ;
    END
  END o[124]
  PIN o[125]
    DIRECTION OUTPUT ;
    USE SIGNAL ;
    PORT
      LAYER M4 ;
        RECT  21.516 15.792 21.6 15.816 ;
    END
  END o[125]
  PIN o[126]
    DIRECTION OUTPUT ;
    USE SIGNAL ;
    PORT
      LAYER M4 ;
        RECT  21.516 15.888 21.6 15.912 ;
    END
  END o[126]
  PIN o[127]
    DIRECTION OUTPUT ;
    USE SIGNAL ;
    PORT
      LAYER M4 ;
        RECT  21.516 15.984 21.6 16.008 ;
    END
  END o[127]
  PIN o[128]
    DIRECTION OUTPUT ;
    USE SIGNAL ;
    PORT
      LAYER M4 ;
        RECT  21.516 22.992 21.6 23.016 ;
    END
  END o[128]
  PIN o[129]
    DIRECTION OUTPUT ;
    USE SIGNAL ;
    PORT
      LAYER M4 ;
        RECT  21.516 23.088 21.6 23.112 ;
    END
  END o[129]
  PIN o[12]
    DIRECTION OUTPUT ;
    USE SIGNAL ;
    PORT
      LAYER M4 ;
        RECT  21.516 4.944 21.6 4.968 ;
    END
  END o[12]
  PIN o[130]
    DIRECTION OUTPUT ;
    USE SIGNAL ;
    PORT
      LAYER M4 ;
        RECT  21.516 23.184 21.6 23.208 ;
    END
  END o[130]
  PIN o[131]
    DIRECTION OUTPUT ;
    USE SIGNAL ;
    PORT
      LAYER M4 ;
        RECT  21.516 23.28 21.6 23.304 ;
    END
  END o[131]
  PIN o[132]
    DIRECTION OUTPUT ;
    USE SIGNAL ;
    PORT
      LAYER M4 ;
        RECT  21.516 23.376 21.6 23.4 ;
    END
  END o[132]
  PIN o[133]
    DIRECTION OUTPUT ;
    USE SIGNAL ;
    PORT
      LAYER M4 ;
        RECT  21.516 23.472 21.6 23.496 ;
    END
  END o[133]
  PIN o[134]
    DIRECTION OUTPUT ;
    USE SIGNAL ;
    PORT
      LAYER M4 ;
        RECT  21.516 23.568 21.6 23.592 ;
    END
  END o[134]
  PIN o[135]
    DIRECTION OUTPUT ;
    USE SIGNAL ;
    PORT
      LAYER M4 ;
        RECT  21.516 23.664 21.6 23.688 ;
    END
  END o[135]
  PIN o[136]
    DIRECTION OUTPUT ;
    USE SIGNAL ;
    PORT
      LAYER M4 ;
        RECT  21.516 23.76 21.6 23.784 ;
    END
  END o[136]
  PIN o[137]
    DIRECTION OUTPUT ;
    USE SIGNAL ;
    PORT
      LAYER M4 ;
        RECT  21.516 23.856 21.6 23.88 ;
    END
  END o[137]
  PIN o[138]
    DIRECTION OUTPUT ;
    USE SIGNAL ;
    PORT
      LAYER M4 ;
        RECT  21.516 23.952 21.6 23.976 ;
    END
  END o[138]
  PIN o[139]
    DIRECTION OUTPUT ;
    USE SIGNAL ;
    PORT
      LAYER M4 ;
        RECT  21.516 24.048 21.6 24.072 ;
    END
  END o[139]
  PIN o[13]
    DIRECTION OUTPUT ;
    USE SIGNAL ;
    PORT
      LAYER M4 ;
        RECT  21.516 5.04 21.6 5.064 ;
    END
  END o[13]
  PIN o[140]
    DIRECTION OUTPUT ;
    USE SIGNAL ;
    PORT
      LAYER M4 ;
        RECT  21.516 24.144 21.6 24.168 ;
    END
  END o[140]
  PIN o[141]
    DIRECTION OUTPUT ;
    USE SIGNAL ;
    PORT
      LAYER M4 ;
        RECT  21.516 24.24 21.6 24.264 ;
    END
  END o[141]
  PIN o[142]
    DIRECTION OUTPUT ;
    USE SIGNAL ;
    PORT
      LAYER M4 ;
        RECT  21.516 24.336 21.6 24.36 ;
    END
  END o[142]
  PIN o[143]
    DIRECTION OUTPUT ;
    USE SIGNAL ;
    PORT
      LAYER M4 ;
        RECT  21.516 24.432 21.6 24.456 ;
    END
  END o[143]
  PIN o[144]
    DIRECTION OUTPUT ;
    USE SIGNAL ;
    PORT
      LAYER M4 ;
        RECT  21.516 24.528 21.6 24.552 ;
    END
  END o[144]
  PIN o[145]
    DIRECTION OUTPUT ;
    USE SIGNAL ;
    PORT
      LAYER M4 ;
        RECT  21.516 24.624 21.6 24.648 ;
    END
  END o[145]
  PIN o[146]
    DIRECTION OUTPUT ;
    USE SIGNAL ;
    PORT
      LAYER M4 ;
        RECT  21.516 24.72 21.6 24.744 ;
    END
  END o[146]
  PIN o[147]
    DIRECTION OUTPUT ;
    USE SIGNAL ;
    PORT
      LAYER M4 ;
        RECT  21.516 24.816 21.6 24.84 ;
    END
  END o[147]
  PIN o[148]
    DIRECTION OUTPUT ;
    USE SIGNAL ;
    PORT
      LAYER M4 ;
        RECT  21.516 24.912 21.6 24.936 ;
    END
  END o[148]
  PIN o[149]
    DIRECTION OUTPUT ;
    USE SIGNAL ;
    PORT
      LAYER M4 ;
        RECT  21.516 25.008 21.6 25.032 ;
    END
  END o[149]
  PIN o[14]
    DIRECTION OUTPUT ;
    USE SIGNAL ;
    PORT
      LAYER M4 ;
        RECT  21.516 5.136 21.6 5.16 ;
    END
  END o[14]
  PIN o[150]
    DIRECTION OUTPUT ;
    USE SIGNAL ;
    PORT
      LAYER M4 ;
        RECT  21.516 25.104 21.6 25.128 ;
    END
  END o[150]
  PIN o[151]
    DIRECTION OUTPUT ;
    USE SIGNAL ;
    PORT
      LAYER M4 ;
        RECT  21.516 25.2 21.6 25.224 ;
    END
  END o[151]
  PIN o[152]
    DIRECTION OUTPUT ;
    USE SIGNAL ;
    PORT
      LAYER M4 ;
        RECT  21.516 25.296 21.6 25.32 ;
    END
  END o[152]
  PIN o[153]
    DIRECTION OUTPUT ;
    USE SIGNAL ;
    PORT
      LAYER M4 ;
        RECT  21.516 25.392 21.6 25.416 ;
    END
  END o[153]
  PIN o[154]
    DIRECTION OUTPUT ;
    USE SIGNAL ;
    PORT
      LAYER M4 ;
        RECT  21.516 25.488 21.6 25.512 ;
    END
  END o[154]
  PIN o[155]
    DIRECTION OUTPUT ;
    USE SIGNAL ;
    PORT
      LAYER M4 ;
        RECT  21.516 25.584 21.6 25.608 ;
    END
  END o[155]
  PIN o[156]
    DIRECTION OUTPUT ;
    USE SIGNAL ;
    PORT
      LAYER M4 ;
        RECT  21.516 25.68 21.6 25.704 ;
    END
  END o[156]
  PIN o[157]
    DIRECTION OUTPUT ;
    USE SIGNAL ;
    PORT
      LAYER M4 ;
        RECT  21.516 25.776 21.6 25.8 ;
    END
  END o[157]
  PIN o[158]
    DIRECTION OUTPUT ;
    USE SIGNAL ;
    PORT
      LAYER M4 ;
        RECT  21.516 25.872 21.6 25.896 ;
    END
  END o[158]
  PIN o[159]
    DIRECTION OUTPUT ;
    USE SIGNAL ;
    PORT
      LAYER M4 ;
        RECT  21.516 25.968 21.6 25.992 ;
    END
  END o[159]
  PIN o[15]
    DIRECTION OUTPUT ;
    USE SIGNAL ;
    PORT
      LAYER M4 ;
        RECT  21.516 5.232 21.6 5.256 ;
    END
  END o[15]
  PIN o[160]
    DIRECTION OUTPUT ;
    USE SIGNAL ;
    PORT
      LAYER M4 ;
        RECT  21.516 0.72 21.6 0.744 ;
    END
  END o[160]
  PIN o[161]
    DIRECTION OUTPUT ;
    USE SIGNAL ;
    PORT
      LAYER M4 ;
        RECT  21.516 0.816 21.6 0.84 ;
    END
  END o[161]
  PIN o[162]
    DIRECTION OUTPUT ;
    USE SIGNAL ;
    PORT
      LAYER M4 ;
        RECT  21.516 0.912 21.6 0.936 ;
    END
  END o[162]
  PIN o[163]
    DIRECTION OUTPUT ;
    USE SIGNAL ;
    PORT
      LAYER M4 ;
        RECT  21.516 1.008 21.6 1.032 ;
    END
  END o[163]
  PIN o[164]
    DIRECTION OUTPUT ;
    USE SIGNAL ;
    PORT
      LAYER M4 ;
        RECT  21.516 1.104 21.6 1.128 ;
    END
  END o[164]
  PIN o[165]
    DIRECTION OUTPUT ;
    USE SIGNAL ;
    PORT
      LAYER M4 ;
        RECT  21.516 1.2 21.6 1.224 ;
    END
  END o[165]
  PIN o[166]
    DIRECTION OUTPUT ;
    USE SIGNAL ;
    PORT
      LAYER M4 ;
        RECT  21.516 1.296 21.6 1.32 ;
    END
  END o[166]
  PIN o[167]
    DIRECTION OUTPUT ;
    USE SIGNAL ;
    PORT
      LAYER M4 ;
        RECT  21.516 1.392 21.6 1.416 ;
    END
  END o[167]
  PIN o[168]
    DIRECTION OUTPUT ;
    USE SIGNAL ;
    PORT
      LAYER M4 ;
        RECT  21.516 1.488 21.6 1.512 ;
    END
  END o[168]
  PIN o[169]
    DIRECTION OUTPUT ;
    USE SIGNAL ;
    PORT
      LAYER M4 ;
        RECT  21.516 1.584 21.6 1.608 ;
    END
  END o[169]
  PIN o[16]
    DIRECTION OUTPUT ;
    USE SIGNAL ;
    PORT
      LAYER M4 ;
        RECT  21.516 5.328 21.6 5.352 ;
    END
  END o[16]
  PIN o[170]
    DIRECTION OUTPUT ;
    USE SIGNAL ;
    PORT
      LAYER M4 ;
        RECT  21.516 1.68 21.6 1.704 ;
    END
  END o[170]
  PIN o[171]
    DIRECTION OUTPUT ;
    USE SIGNAL ;
    PORT
      LAYER M4 ;
        RECT  21.516 1.776 21.6 1.8 ;
    END
  END o[171]
  PIN o[172]
    DIRECTION OUTPUT ;
    USE SIGNAL ;
    PORT
      LAYER M4 ;
        RECT  21.516 1.872 21.6 1.896 ;
    END
  END o[172]
  PIN o[173]
    DIRECTION OUTPUT ;
    USE SIGNAL ;
    PORT
      LAYER M4 ;
        RECT  21.516 1.968 21.6 1.992 ;
    END
  END o[173]
  PIN o[174]
    DIRECTION OUTPUT ;
    USE SIGNAL ;
    PORT
      LAYER M4 ;
        RECT  21.516 2.064 21.6 2.088 ;
    END
  END o[174]
  PIN o[175]
    DIRECTION OUTPUT ;
    USE SIGNAL ;
    PORT
      LAYER M4 ;
        RECT  21.516 2.16 21.6 2.184 ;
    END
  END o[175]
  PIN o[176]
    DIRECTION OUTPUT ;
    USE SIGNAL ;
    PORT
      LAYER M4 ;
        RECT  21.516 2.256 21.6 2.28 ;
    END
  END o[176]
  PIN o[177]
    DIRECTION OUTPUT ;
    USE SIGNAL ;
    PORT
      LAYER M4 ;
        RECT  21.516 2.352 21.6 2.376 ;
    END
  END o[177]
  PIN o[178]
    DIRECTION OUTPUT ;
    USE SIGNAL ;
    PORT
      LAYER M4 ;
        RECT  21.516 2.448 21.6 2.472 ;
    END
  END o[178]
  PIN o[179]
    DIRECTION OUTPUT ;
    USE SIGNAL ;
    PORT
      LAYER M4 ;
        RECT  21.516 2.544 21.6 2.568 ;
    END
  END o[179]
  PIN o[17]
    DIRECTION OUTPUT ;
    USE SIGNAL ;
    PORT
      LAYER M4 ;
        RECT  21.516 5.424 21.6 5.448 ;
    END
  END o[17]
  PIN o[180]
    DIRECTION OUTPUT ;
    USE SIGNAL ;
    PORT
      LAYER M4 ;
        RECT  21.516 2.64 21.6 2.664 ;
    END
  END o[180]
  PIN o[181]
    DIRECTION OUTPUT ;
    USE SIGNAL ;
    PORT
      LAYER M4 ;
        RECT  21.516 2.736 21.6 2.76 ;
    END
  END o[181]
  PIN o[182]
    DIRECTION OUTPUT ;
    USE SIGNAL ;
    PORT
      LAYER M4 ;
        RECT  21.516 2.832 21.6 2.856 ;
    END
  END o[182]
  PIN o[183]
    DIRECTION OUTPUT ;
    USE SIGNAL ;
    PORT
      LAYER M4 ;
        RECT  21.516 2.928 21.6 2.952 ;
    END
  END o[183]
  PIN o[184]
    DIRECTION OUTPUT ;
    USE SIGNAL ;
    PORT
      LAYER M4 ;
        RECT  21.516 3.024 21.6 3.048 ;
    END
  END o[184]
  PIN o[185]
    DIRECTION OUTPUT ;
    USE SIGNAL ;
    PORT
      LAYER M4 ;
        RECT  21.516 3.12 21.6 3.144 ;
    END
  END o[185]
  PIN o[186]
    DIRECTION OUTPUT ;
    USE SIGNAL ;
    PORT
      LAYER M4 ;
        RECT  21.516 3.216 21.6 3.24 ;
    END
  END o[186]
  PIN o[187]
    DIRECTION OUTPUT ;
    USE SIGNAL ;
    PORT
      LAYER M4 ;
        RECT  21.516 3.312 21.6 3.336 ;
    END
  END o[187]
  PIN o[188]
    DIRECTION OUTPUT ;
    USE SIGNAL ;
    PORT
      LAYER M4 ;
        RECT  21.516 3.408 21.6 3.432 ;
    END
  END o[188]
  PIN o[189]
    DIRECTION OUTPUT ;
    USE SIGNAL ;
    PORT
      LAYER M4 ;
        RECT  21.516 3.504 21.6 3.528 ;
    END
  END o[189]
  PIN o[18]
    DIRECTION OUTPUT ;
    USE SIGNAL ;
    PORT
      LAYER M4 ;
        RECT  21.516 5.52 21.6 5.544 ;
    END
  END o[18]
  PIN o[190]
    DIRECTION OUTPUT ;
    USE SIGNAL ;
    PORT
      LAYER M4 ;
        RECT  21.516 3.6 21.6 3.624 ;
    END
  END o[190]
  PIN o[191]
    DIRECTION OUTPUT ;
    USE SIGNAL ;
    PORT
      LAYER M4 ;
        RECT  21.516 3.696 21.6 3.72 ;
    END
  END o[191]
  PIN o[192]
    DIRECTION OUTPUT ;
    USE SIGNAL ;
    PORT
      LAYER M4 ;
        RECT  21.516 6.864 21.6 6.888 ;
    END
  END o[192]
  PIN o[193]
    DIRECTION OUTPUT ;
    USE SIGNAL ;
    PORT
      LAYER M4 ;
        RECT  21.516 6.96 21.6 6.984 ;
    END
  END o[193]
  PIN o[194]
    DIRECTION OUTPUT ;
    USE SIGNAL ;
    PORT
      LAYER M4 ;
        RECT  21.516 7.056 21.6 7.08 ;
    END
  END o[194]
  PIN o[195]
    DIRECTION OUTPUT ;
    USE SIGNAL ;
    PORT
      LAYER M4 ;
        RECT  21.516 7.152 21.6 7.176 ;
    END
  END o[195]
  PIN o[196]
    DIRECTION OUTPUT ;
    USE SIGNAL ;
    PORT
      LAYER M4 ;
        RECT  21.516 7.248 21.6 7.272 ;
    END
  END o[196]
  PIN o[197]
    DIRECTION OUTPUT ;
    USE SIGNAL ;
    PORT
      LAYER M4 ;
        RECT  21.516 7.344 21.6 7.368 ;
    END
  END o[197]
  PIN o[198]
    DIRECTION OUTPUT ;
    USE SIGNAL ;
    PORT
      LAYER M4 ;
        RECT  21.516 7.44 21.6 7.464 ;
    END
  END o[198]
  PIN o[199]
    DIRECTION OUTPUT ;
    USE SIGNAL ;
    PORT
      LAYER M4 ;
        RECT  21.516 7.536 21.6 7.56 ;
    END
  END o[199]
  PIN o[19]
    DIRECTION OUTPUT ;
    USE SIGNAL ;
    PORT
      LAYER M4 ;
        RECT  21.516 5.616 21.6 5.64 ;
    END
  END o[19]
  PIN o[1]
    DIRECTION OUTPUT ;
    USE SIGNAL ;
    PORT
      LAYER M4 ;
        RECT  21.516 3.888 21.6 3.912 ;
    END
  END o[1]
  PIN o[200]
    DIRECTION OUTPUT ;
    USE SIGNAL ;
    PORT
      LAYER M4 ;
        RECT  21.516 7.632 21.6 7.656 ;
    END
  END o[200]
  PIN o[201]
    DIRECTION OUTPUT ;
    USE SIGNAL ;
    PORT
      LAYER M4 ;
        RECT  21.516 7.728 21.6 7.752 ;
    END
  END o[201]
  PIN o[202]
    DIRECTION OUTPUT ;
    USE SIGNAL ;
    PORT
      LAYER M4 ;
        RECT  21.516 7.824 21.6 7.848 ;
    END
  END o[202]
  PIN o[203]
    DIRECTION OUTPUT ;
    USE SIGNAL ;
    PORT
      LAYER M4 ;
        RECT  21.516 7.92 21.6 7.944 ;
    END
  END o[203]
  PIN o[204]
    DIRECTION OUTPUT ;
    USE SIGNAL ;
    PORT
      LAYER M4 ;
        RECT  21.516 8.016 21.6 8.04 ;
    END
  END o[204]
  PIN o[205]
    DIRECTION OUTPUT ;
    USE SIGNAL ;
    PORT
      LAYER M4 ;
        RECT  21.516 8.112 21.6 8.136 ;
    END
  END o[205]
  PIN o[206]
    DIRECTION OUTPUT ;
    USE SIGNAL ;
    PORT
      LAYER M4 ;
        RECT  21.516 8.208 21.6 8.232 ;
    END
  END o[206]
  PIN o[207]
    DIRECTION OUTPUT ;
    USE SIGNAL ;
    PORT
      LAYER M4 ;
        RECT  21.516 8.304 21.6 8.328 ;
    END
  END o[207]
  PIN o[208]
    DIRECTION OUTPUT ;
    USE SIGNAL ;
    PORT
      LAYER M4 ;
        RECT  21.516 8.4 21.6 8.424 ;
    END
  END o[208]
  PIN o[209]
    DIRECTION OUTPUT ;
    USE SIGNAL ;
    PORT
      LAYER M4 ;
        RECT  21.516 8.496 21.6 8.52 ;
    END
  END o[209]
  PIN o[20]
    DIRECTION OUTPUT ;
    USE SIGNAL ;
    PORT
      LAYER M4 ;
        RECT  21.516 5.712 21.6 5.736 ;
    END
  END o[20]
  PIN o[210]
    DIRECTION OUTPUT ;
    USE SIGNAL ;
    PORT
      LAYER M4 ;
        RECT  21.516 8.592 21.6 8.616 ;
    END
  END o[210]
  PIN o[211]
    DIRECTION OUTPUT ;
    USE SIGNAL ;
    PORT
      LAYER M4 ;
        RECT  21.516 8.688 21.6 8.712 ;
    END
  END o[211]
  PIN o[212]
    DIRECTION OUTPUT ;
    USE SIGNAL ;
    PORT
      LAYER M4 ;
        RECT  21.516 8.784 21.6 8.808 ;
    END
  END o[212]
  PIN o[213]
    DIRECTION OUTPUT ;
    USE SIGNAL ;
    PORT
      LAYER M4 ;
        RECT  21.516 8.88 21.6 8.904 ;
    END
  END o[213]
  PIN o[214]
    DIRECTION OUTPUT ;
    USE SIGNAL ;
    PORT
      LAYER M4 ;
        RECT  21.516 8.976 21.6 9 ;
    END
  END o[214]
  PIN o[215]
    DIRECTION OUTPUT ;
    USE SIGNAL ;
    PORT
      LAYER M4 ;
        RECT  21.516 9.072 21.6 9.096 ;
    END
  END o[215]
  PIN o[216]
    DIRECTION OUTPUT ;
    USE SIGNAL ;
    PORT
      LAYER M4 ;
        RECT  21.516 9.168 21.6 9.192 ;
    END
  END o[216]
  PIN o[217]
    DIRECTION OUTPUT ;
    USE SIGNAL ;
    PORT
      LAYER M4 ;
        RECT  21.516 9.264 21.6 9.288 ;
    END
  END o[217]
  PIN o[218]
    DIRECTION OUTPUT ;
    USE SIGNAL ;
    PORT
      LAYER M4 ;
        RECT  21.516 9.36 21.6 9.384 ;
    END
  END o[218]
  PIN o[219]
    DIRECTION OUTPUT ;
    USE SIGNAL ;
    PORT
      LAYER M4 ;
        RECT  21.516 9.456 21.6 9.48 ;
    END
  END o[219]
  PIN o[21]
    DIRECTION OUTPUT ;
    USE SIGNAL ;
    PORT
      LAYER M4 ;
        RECT  21.516 5.808 21.6 5.832 ;
    END
  END o[21]
  PIN o[220]
    DIRECTION OUTPUT ;
    USE SIGNAL ;
    PORT
      LAYER M4 ;
        RECT  21.516 9.552 21.6 9.576 ;
    END
  END o[220]
  PIN o[221]
    DIRECTION OUTPUT ;
    USE SIGNAL ;
    PORT
      LAYER M4 ;
        RECT  21.516 9.648 21.6 9.672 ;
    END
  END o[221]
  PIN o[222]
    DIRECTION OUTPUT ;
    USE SIGNAL ;
    PORT
      LAYER M4 ;
        RECT  21.516 9.744 21.6 9.768 ;
    END
  END o[222]
  PIN o[223]
    DIRECTION OUTPUT ;
    USE SIGNAL ;
    PORT
      LAYER M4 ;
        RECT  21.516 9.84 21.6 9.864 ;
    END
  END o[223]
  PIN o[224]
    DIRECTION OUTPUT ;
    USE SIGNAL ;
    PORT
      LAYER M4 ;
        RECT  21.516 29.136 21.6 29.16 ;
    END
  END o[224]
  PIN o[225]
    DIRECTION OUTPUT ;
    USE SIGNAL ;
    PORT
      LAYER M4 ;
        RECT  21.516 29.232 21.6 29.256 ;
    END
  END o[225]
  PIN o[226]
    DIRECTION OUTPUT ;
    USE SIGNAL ;
    PORT
      LAYER M4 ;
        RECT  21.516 29.328 21.6 29.352 ;
    END
  END o[226]
  PIN o[227]
    DIRECTION OUTPUT ;
    USE SIGNAL ;
    PORT
      LAYER M4 ;
        RECT  21.516 29.424 21.6 29.448 ;
    END
  END o[227]
  PIN o[228]
    DIRECTION OUTPUT ;
    USE SIGNAL ;
    PORT
      LAYER M4 ;
        RECT  21.516 29.52 21.6 29.544 ;
    END
  END o[228]
  PIN o[229]
    DIRECTION OUTPUT ;
    USE SIGNAL ;
    PORT
      LAYER M4 ;
        RECT  21.516 29.616 21.6 29.64 ;
    END
  END o[229]
  PIN o[22]
    DIRECTION OUTPUT ;
    USE SIGNAL ;
    PORT
      LAYER M4 ;
        RECT  21.516 5.904 21.6 5.928 ;
    END
  END o[22]
  PIN o[230]
    DIRECTION OUTPUT ;
    USE SIGNAL ;
    PORT
      LAYER M4 ;
        RECT  21.516 29.712 21.6 29.736 ;
    END
  END o[230]
  PIN o[231]
    DIRECTION OUTPUT ;
    USE SIGNAL ;
    PORT
      LAYER M4 ;
        RECT  21.516 29.808 21.6 29.832 ;
    END
  END o[231]
  PIN o[232]
    DIRECTION OUTPUT ;
    USE SIGNAL ;
    PORT
      LAYER M4 ;
        RECT  21.516 29.904 21.6 29.928 ;
    END
  END o[232]
  PIN o[233]
    DIRECTION OUTPUT ;
    USE SIGNAL ;
    PORT
      LAYER M4 ;
        RECT  21.516 30 21.6 30.024 ;
    END
  END o[233]
  PIN o[234]
    DIRECTION OUTPUT ;
    USE SIGNAL ;
    PORT
      LAYER M4 ;
        RECT  21.516 30.096 21.6 30.12 ;
    END
  END o[234]
  PIN o[235]
    DIRECTION OUTPUT ;
    USE SIGNAL ;
    PORT
      LAYER M4 ;
        RECT  21.516 30.192 21.6 30.216 ;
    END
  END o[235]
  PIN o[236]
    DIRECTION OUTPUT ;
    USE SIGNAL ;
    PORT
      LAYER M4 ;
        RECT  21.516 30.288 21.6 30.312 ;
    END
  END o[236]
  PIN o[237]
    DIRECTION OUTPUT ;
    USE SIGNAL ;
    PORT
      LAYER M4 ;
        RECT  21.516 30.384 21.6 30.408 ;
    END
  END o[237]
  PIN o[238]
    DIRECTION OUTPUT ;
    USE SIGNAL ;
    PORT
      LAYER M4 ;
        RECT  21.516 30.48 21.6 30.504 ;
    END
  END o[238]
  PIN o[239]
    DIRECTION OUTPUT ;
    USE SIGNAL ;
    PORT
      LAYER M4 ;
        RECT  21.516 30.576 21.6 30.6 ;
    END
  END o[239]
  PIN o[23]
    DIRECTION OUTPUT ;
    USE SIGNAL ;
    PORT
      LAYER M4 ;
        RECT  21.516 6 21.6 6.024 ;
    END
  END o[23]
  PIN o[240]
    DIRECTION OUTPUT ;
    USE SIGNAL ;
    PORT
      LAYER M4 ;
        RECT  21.516 30.672 21.6 30.696 ;
    END
  END o[240]
  PIN o[241]
    DIRECTION OUTPUT ;
    USE SIGNAL ;
    PORT
      LAYER M4 ;
        RECT  21.516 30.768 21.6 30.792 ;
    END
  END o[241]
  PIN o[242]
    DIRECTION OUTPUT ;
    USE SIGNAL ;
    PORT
      LAYER M4 ;
        RECT  21.516 30.864 21.6 30.888 ;
    END
  END o[242]
  PIN o[243]
    DIRECTION OUTPUT ;
    USE SIGNAL ;
    PORT
      LAYER M4 ;
        RECT  21.516 30.96 21.6 30.984 ;
    END
  END o[243]
  PIN o[244]
    DIRECTION OUTPUT ;
    USE SIGNAL ;
    PORT
      LAYER M4 ;
        RECT  21.516 31.056 21.6 31.08 ;
    END
  END o[244]
  PIN o[245]
    DIRECTION OUTPUT ;
    USE SIGNAL ;
    PORT
      LAYER M4 ;
        RECT  21.516 31.152 21.6 31.176 ;
    END
  END o[245]
  PIN o[246]
    DIRECTION OUTPUT ;
    USE SIGNAL ;
    PORT
      LAYER M4 ;
        RECT  21.516 31.248 21.6 31.272 ;
    END
  END o[246]
  PIN o[247]
    DIRECTION OUTPUT ;
    USE SIGNAL ;
    PORT
      LAYER M4 ;
        RECT  21.516 31.344 21.6 31.368 ;
    END
  END o[247]
  PIN o[248]
    DIRECTION OUTPUT ;
    USE SIGNAL ;
    PORT
      LAYER M4 ;
        RECT  21.516 31.44 21.6 31.464 ;
    END
  END o[248]
  PIN o[249]
    DIRECTION OUTPUT ;
    USE SIGNAL ;
    PORT
      LAYER M4 ;
        RECT  21.516 31.536 21.6 31.56 ;
    END
  END o[249]
  PIN o[24]
    DIRECTION OUTPUT ;
    USE SIGNAL ;
    PORT
      LAYER M4 ;
        RECT  21.516 6.096 21.6 6.12 ;
    END
  END o[24]
  PIN o[250]
    DIRECTION OUTPUT ;
    USE SIGNAL ;
    PORT
      LAYER M4 ;
        RECT  21.516 31.632 21.6 31.656 ;
    END
  END o[250]
  PIN o[251]
    DIRECTION OUTPUT ;
    USE SIGNAL ;
    PORT
      LAYER M4 ;
        RECT  21.516 31.728 21.6 31.752 ;
    END
  END o[251]
  PIN o[252]
    DIRECTION OUTPUT ;
    USE SIGNAL ;
    PORT
      LAYER M4 ;
        RECT  21.516 31.824 21.6 31.848 ;
    END
  END o[252]
  PIN o[253]
    DIRECTION OUTPUT ;
    USE SIGNAL ;
    PORT
      LAYER M4 ;
        RECT  21.516 31.92 21.6 31.944 ;
    END
  END o[253]
  PIN o[254]
    DIRECTION OUTPUT ;
    USE SIGNAL ;
    PORT
      LAYER M4 ;
        RECT  21.516 32.016 21.6 32.04 ;
    END
  END o[254]
  PIN o[255]
    DIRECTION OUTPUT ;
    USE SIGNAL ;
    PORT
      LAYER M4 ;
        RECT  21.516 32.112 21.6 32.136 ;
    END
  END o[255]
  PIN o[256]
    DIRECTION OUTPUT ;
    USE SIGNAL ;
    PORT
      LAYER M4 ;
        RECT  21.516 16.08 21.6 16.104 ;
    END
  END o[256]
  PIN o[257]
    DIRECTION OUTPUT ;
    USE SIGNAL ;
    PORT
      LAYER M4 ;
        RECT  21.516 16.176 21.6 16.2 ;
    END
  END o[257]
  PIN o[258]
    DIRECTION OUTPUT ;
    USE SIGNAL ;
    PORT
      LAYER M4 ;
        RECT  21.516 16.272 21.6 16.296 ;
    END
  END o[258]
  PIN o[259]
    DIRECTION OUTPUT ;
    USE SIGNAL ;
    PORT
      LAYER M4 ;
        RECT  21.516 16.368 21.6 16.392 ;
    END
  END o[259]
  PIN o[25]
    DIRECTION OUTPUT ;
    USE SIGNAL ;
    PORT
      LAYER M4 ;
        RECT  21.516 6.192 21.6 6.216 ;
    END
  END o[25]
  PIN o[260]
    DIRECTION OUTPUT ;
    USE SIGNAL ;
    PORT
      LAYER M4 ;
        RECT  21.516 16.464 21.6 16.488 ;
    END
  END o[260]
  PIN o[261]
    DIRECTION OUTPUT ;
    USE SIGNAL ;
    PORT
      LAYER M4 ;
        RECT  21.516 16.56 21.6 16.584 ;
    END
  END o[261]
  PIN o[262]
    DIRECTION OUTPUT ;
    USE SIGNAL ;
    PORT
      LAYER M4 ;
        RECT  21.516 16.656 21.6 16.68 ;
    END
  END o[262]
  PIN o[263]
    DIRECTION OUTPUT ;
    USE SIGNAL ;
    PORT
      LAYER M4 ;
        RECT  21.516 16.752 21.6 16.776 ;
    END
  END o[263]
  PIN o[264]
    DIRECTION OUTPUT ;
    USE SIGNAL ;
    PORT
      LAYER M4 ;
        RECT  21.516 16.848 21.6 16.872 ;
    END
  END o[264]
  PIN o[265]
    DIRECTION OUTPUT ;
    USE SIGNAL ;
    PORT
      LAYER M4 ;
        RECT  21.516 16.944 21.6 16.968 ;
    END
  END o[265]
  PIN o[266]
    DIRECTION OUTPUT ;
    USE SIGNAL ;
    PORT
      LAYER M4 ;
        RECT  21.516 17.04 21.6 17.064 ;
    END
  END o[266]
  PIN o[267]
    DIRECTION OUTPUT ;
    USE SIGNAL ;
    PORT
      LAYER M4 ;
        RECT  21.516 17.136 21.6 17.16 ;
    END
  END o[267]
  PIN o[268]
    DIRECTION OUTPUT ;
    USE SIGNAL ;
    PORT
      LAYER M4 ;
        RECT  21.516 17.232 21.6 17.256 ;
    END
  END o[268]
  PIN o[269]
    DIRECTION OUTPUT ;
    USE SIGNAL ;
    PORT
      LAYER M4 ;
        RECT  21.516 17.328 21.6 17.352 ;
    END
  END o[269]
  PIN o[26]
    DIRECTION OUTPUT ;
    USE SIGNAL ;
    PORT
      LAYER M4 ;
        RECT  21.516 6.288 21.6 6.312 ;
    END
  END o[26]
  PIN o[270]
    DIRECTION OUTPUT ;
    USE SIGNAL ;
    PORT
      LAYER M4 ;
        RECT  21.516 17.424 21.6 17.448 ;
    END
  END o[270]
  PIN o[271]
    DIRECTION OUTPUT ;
    USE SIGNAL ;
    PORT
      LAYER M4 ;
        RECT  21.516 17.52 21.6 17.544 ;
    END
  END o[271]
  PIN o[272]
    DIRECTION OUTPUT ;
    USE SIGNAL ;
    PORT
      LAYER M4 ;
        RECT  21.516 17.616 21.6 17.64 ;
    END
  END o[272]
  PIN o[273]
    DIRECTION OUTPUT ;
    USE SIGNAL ;
    PORT
      LAYER M4 ;
        RECT  21.516 17.712 21.6 17.736 ;
    END
  END o[273]
  PIN o[274]
    DIRECTION OUTPUT ;
    USE SIGNAL ;
    PORT
      LAYER M4 ;
        RECT  21.516 17.808 21.6 17.832 ;
    END
  END o[274]
  PIN o[275]
    DIRECTION OUTPUT ;
    USE SIGNAL ;
    PORT
      LAYER M4 ;
        RECT  21.516 17.904 21.6 17.928 ;
    END
  END o[275]
  PIN o[276]
    DIRECTION OUTPUT ;
    USE SIGNAL ;
    PORT
      LAYER M4 ;
        RECT  21.516 18 21.6 18.024 ;
    END
  END o[276]
  PIN o[277]
    DIRECTION OUTPUT ;
    USE SIGNAL ;
    PORT
      LAYER M4 ;
        RECT  21.516 18.096 21.6 18.12 ;
    END
  END o[277]
  PIN o[278]
    DIRECTION OUTPUT ;
    USE SIGNAL ;
    PORT
      LAYER M4 ;
        RECT  21.516 18.192 21.6 18.216 ;
    END
  END o[278]
  PIN o[279]
    DIRECTION OUTPUT ;
    USE SIGNAL ;
    PORT
      LAYER M4 ;
        RECT  21.516 18.288 21.6 18.312 ;
    END
  END o[279]
  PIN o[27]
    DIRECTION OUTPUT ;
    USE SIGNAL ;
    PORT
      LAYER M4 ;
        RECT  21.516 6.384 21.6 6.408 ;
    END
  END o[27]
  PIN o[280]
    DIRECTION OUTPUT ;
    USE SIGNAL ;
    PORT
      LAYER M4 ;
        RECT  21.516 18.384 21.6 18.408 ;
    END
  END o[280]
  PIN o[281]
    DIRECTION OUTPUT ;
    USE SIGNAL ;
    PORT
      LAYER M4 ;
        RECT  21.516 18.48 21.6 18.504 ;
    END
  END o[281]
  PIN o[282]
    DIRECTION OUTPUT ;
    USE SIGNAL ;
    PORT
      LAYER M4 ;
        RECT  21.516 18.576 21.6 18.6 ;
    END
  END o[282]
  PIN o[283]
    DIRECTION OUTPUT ;
    USE SIGNAL ;
    PORT
      LAYER M4 ;
        RECT  21.516 18.672 21.6 18.696 ;
    END
  END o[283]
  PIN o[284]
    DIRECTION OUTPUT ;
    USE SIGNAL ;
    PORT
      LAYER M4 ;
        RECT  21.516 18.768 21.6 18.792 ;
    END
  END o[284]
  PIN o[285]
    DIRECTION OUTPUT ;
    USE SIGNAL ;
    PORT
      LAYER M4 ;
        RECT  21.516 18.864 21.6 18.888 ;
    END
  END o[285]
  PIN o[286]
    DIRECTION OUTPUT ;
    USE SIGNAL ;
    PORT
      LAYER M4 ;
        RECT  21.516 18.96 21.6 18.984 ;
    END
  END o[286]
  PIN o[287]
    DIRECTION OUTPUT ;
    USE SIGNAL ;
    PORT
      LAYER M4 ;
        RECT  21.516 19.056 21.6 19.08 ;
    END
  END o[287]
  PIN o[288]
    DIRECTION OUTPUT ;
    USE SIGNAL ;
    PORT
      LAYER M4 ;
        RECT  21.516 19.92 21.6 19.944 ;
    END
  END o[288]
  PIN o[289]
    DIRECTION OUTPUT ;
    USE SIGNAL ;
    PORT
      LAYER M4 ;
        RECT  21.516 20.016 21.6 20.04 ;
    END
  END o[289]
  PIN o[28]
    DIRECTION OUTPUT ;
    USE SIGNAL ;
    PORT
      LAYER M4 ;
        RECT  21.516 6.48 21.6 6.504 ;
    END
  END o[28]
  PIN o[290]
    DIRECTION OUTPUT ;
    USE SIGNAL ;
    PORT
      LAYER M4 ;
        RECT  21.516 20.112 21.6 20.136 ;
    END
  END o[290]
  PIN o[291]
    DIRECTION OUTPUT ;
    USE SIGNAL ;
    PORT
      LAYER M4 ;
        RECT  21.516 20.208 21.6 20.232 ;
    END
  END o[291]
  PIN o[292]
    DIRECTION OUTPUT ;
    USE SIGNAL ;
    PORT
      LAYER M4 ;
        RECT  21.516 20.304 21.6 20.328 ;
    END
  END o[292]
  PIN o[293]
    DIRECTION OUTPUT ;
    USE SIGNAL ;
    PORT
      LAYER M4 ;
        RECT  21.516 20.4 21.6 20.424 ;
    END
  END o[293]
  PIN o[294]
    DIRECTION OUTPUT ;
    USE SIGNAL ;
    PORT
      LAYER M4 ;
        RECT  21.516 20.496 21.6 20.52 ;
    END
  END o[294]
  PIN o[295]
    DIRECTION OUTPUT ;
    USE SIGNAL ;
    PORT
      LAYER M4 ;
        RECT  21.516 20.592 21.6 20.616 ;
    END
  END o[295]
  PIN o[296]
    DIRECTION OUTPUT ;
    USE SIGNAL ;
    PORT
      LAYER M4 ;
        RECT  21.516 20.688 21.6 20.712 ;
    END
  END o[296]
  PIN o[297]
    DIRECTION OUTPUT ;
    USE SIGNAL ;
    PORT
      LAYER M4 ;
        RECT  21.516 20.784 21.6 20.808 ;
    END
  END o[297]
  PIN o[298]
    DIRECTION OUTPUT ;
    USE SIGNAL ;
    PORT
      LAYER M4 ;
        RECT  21.516 20.88 21.6 20.904 ;
    END
  END o[298]
  PIN o[299]
    DIRECTION OUTPUT ;
    USE SIGNAL ;
    PORT
      LAYER M4 ;
        RECT  21.516 20.976 21.6 21 ;
    END
  END o[299]
  PIN o[29]
    DIRECTION OUTPUT ;
    USE SIGNAL ;
    PORT
      LAYER M4 ;
        RECT  21.516 6.576 21.6 6.6 ;
    END
  END o[29]
  PIN o[2]
    DIRECTION OUTPUT ;
    USE SIGNAL ;
    PORT
      LAYER M4 ;
        RECT  21.516 3.984 21.6 4.008 ;
    END
  END o[2]
  PIN o[300]
    DIRECTION OUTPUT ;
    USE SIGNAL ;
    PORT
      LAYER M4 ;
        RECT  21.516 21.072 21.6 21.096 ;
    END
  END o[300]
  PIN o[301]
    DIRECTION OUTPUT ;
    USE SIGNAL ;
    PORT
      LAYER M4 ;
        RECT  21.516 21.168 21.6 21.192 ;
    END
  END o[301]
  PIN o[302]
    DIRECTION OUTPUT ;
    USE SIGNAL ;
    PORT
      LAYER M4 ;
        RECT  21.516 21.264 21.6 21.288 ;
    END
  END o[302]
  PIN o[303]
    DIRECTION OUTPUT ;
    USE SIGNAL ;
    PORT
      LAYER M4 ;
        RECT  21.516 21.36 21.6 21.384 ;
    END
  END o[303]
  PIN o[30]
    DIRECTION OUTPUT ;
    USE SIGNAL ;
    PORT
      LAYER M4 ;
        RECT  21.516 6.672 21.6 6.696 ;
    END
  END o[30]
  PIN o[31]
    DIRECTION OUTPUT ;
    USE SIGNAL ;
    PORT
      LAYER M4 ;
        RECT  21.516 6.768 21.6 6.792 ;
    END
  END o[31]
  PIN o[32]
    DIRECTION OUTPUT ;
    USE SIGNAL ;
    PORT
      LAYER M4 ;
        RECT  21.516 9.936 21.6 9.96 ;
    END
  END o[32]
  PIN o[33]
    DIRECTION OUTPUT ;
    USE SIGNAL ;
    PORT
      LAYER M4 ;
        RECT  21.516 10.032 21.6 10.056 ;
    END
  END o[33]
  PIN o[34]
    DIRECTION OUTPUT ;
    USE SIGNAL ;
    PORT
      LAYER M4 ;
        RECT  21.516 10.128 21.6 10.152 ;
    END
  END o[34]
  PIN o[35]
    DIRECTION OUTPUT ;
    USE SIGNAL ;
    PORT
      LAYER M4 ;
        RECT  21.516 10.224 21.6 10.248 ;
    END
  END o[35]
  PIN o[36]
    DIRECTION OUTPUT ;
    USE SIGNAL ;
    PORT
      LAYER M4 ;
        RECT  21.516 10.32 21.6 10.344 ;
    END
  END o[36]
  PIN o[37]
    DIRECTION OUTPUT ;
    USE SIGNAL ;
    PORT
      LAYER M4 ;
        RECT  21.516 10.416 21.6 10.44 ;
    END
  END o[37]
  PIN o[38]
    DIRECTION OUTPUT ;
    USE SIGNAL ;
    PORT
      LAYER M4 ;
        RECT  21.516 10.512 21.6 10.536 ;
    END
  END o[38]
  PIN o[39]
    DIRECTION OUTPUT ;
    USE SIGNAL ;
    PORT
      LAYER M4 ;
        RECT  21.516 10.608 21.6 10.632 ;
    END
  END o[39]
  PIN o[3]
    DIRECTION OUTPUT ;
    USE SIGNAL ;
    PORT
      LAYER M4 ;
        RECT  21.516 4.08 21.6 4.104 ;
    END
  END o[3]
  PIN o[40]
    DIRECTION OUTPUT ;
    USE SIGNAL ;
    PORT
      LAYER M4 ;
        RECT  21.516 10.704 21.6 10.728 ;
    END
  END o[40]
  PIN o[41]
    DIRECTION OUTPUT ;
    USE SIGNAL ;
    PORT
      LAYER M4 ;
        RECT  21.516 10.8 21.6 10.824 ;
    END
  END o[41]
  PIN o[42]
    DIRECTION OUTPUT ;
    USE SIGNAL ;
    PORT
      LAYER M4 ;
        RECT  21.516 10.896 21.6 10.92 ;
    END
  END o[42]
  PIN o[43]
    DIRECTION OUTPUT ;
    USE SIGNAL ;
    PORT
      LAYER M4 ;
        RECT  21.516 10.992 21.6 11.016 ;
    END
  END o[43]
  PIN o[44]
    DIRECTION OUTPUT ;
    USE SIGNAL ;
    PORT
      LAYER M4 ;
        RECT  21.516 11.088 21.6 11.112 ;
    END
  END o[44]
  PIN o[45]
    DIRECTION OUTPUT ;
    USE SIGNAL ;
    PORT
      LAYER M4 ;
        RECT  21.516 11.184 21.6 11.208 ;
    END
  END o[45]
  PIN o[46]
    DIRECTION OUTPUT ;
    USE SIGNAL ;
    PORT
      LAYER M4 ;
        RECT  21.516 11.28 21.6 11.304 ;
    END
  END o[46]
  PIN o[47]
    DIRECTION OUTPUT ;
    USE SIGNAL ;
    PORT
      LAYER M4 ;
        RECT  21.516 11.376 21.6 11.4 ;
    END
  END o[47]
  PIN o[48]
    DIRECTION OUTPUT ;
    USE SIGNAL ;
    PORT
      LAYER M4 ;
        RECT  21.516 11.472 21.6 11.496 ;
    END
  END o[48]
  PIN o[49]
    DIRECTION OUTPUT ;
    USE SIGNAL ;
    PORT
      LAYER M4 ;
        RECT  21.516 11.568 21.6 11.592 ;
    END
  END o[49]
  PIN o[4]
    DIRECTION OUTPUT ;
    USE SIGNAL ;
    PORT
      LAYER M4 ;
        RECT  21.516 4.176 21.6 4.2 ;
    END
  END o[4]
  PIN o[50]
    DIRECTION OUTPUT ;
    USE SIGNAL ;
    PORT
      LAYER M4 ;
        RECT  21.516 11.664 21.6 11.688 ;
    END
  END o[50]
  PIN o[51]
    DIRECTION OUTPUT ;
    USE SIGNAL ;
    PORT
      LAYER M4 ;
        RECT  21.516 11.76 21.6 11.784 ;
    END
  END o[51]
  PIN o[52]
    DIRECTION OUTPUT ;
    USE SIGNAL ;
    PORT
      LAYER M4 ;
        RECT  21.516 11.856 21.6 11.88 ;
    END
  END o[52]
  PIN o[53]
    DIRECTION OUTPUT ;
    USE SIGNAL ;
    PORT
      LAYER M4 ;
        RECT  21.516 11.952 21.6 11.976 ;
    END
  END o[53]
  PIN o[54]
    DIRECTION OUTPUT ;
    USE SIGNAL ;
    PORT
      LAYER M4 ;
        RECT  21.516 12.048 21.6 12.072 ;
    END
  END o[54]
  PIN o[55]
    DIRECTION OUTPUT ;
    USE SIGNAL ;
    PORT
      LAYER M4 ;
        RECT  21.516 12.144 21.6 12.168 ;
    END
  END o[55]
  PIN o[56]
    DIRECTION OUTPUT ;
    USE SIGNAL ;
    PORT
      LAYER M4 ;
        RECT  21.516 12.24 21.6 12.264 ;
    END
  END o[56]
  PIN o[57]
    DIRECTION OUTPUT ;
    USE SIGNAL ;
    PORT
      LAYER M4 ;
        RECT  21.516 12.336 21.6 12.36 ;
    END
  END o[57]
  PIN o[58]
    DIRECTION OUTPUT ;
    USE SIGNAL ;
    PORT
      LAYER M4 ;
        RECT  21.516 12.432 21.6 12.456 ;
    END
  END o[58]
  PIN o[59]
    DIRECTION OUTPUT ;
    USE SIGNAL ;
    PORT
      LAYER M4 ;
        RECT  21.516 12.528 21.6 12.552 ;
    END
  END o[59]
  PIN o[5]
    DIRECTION OUTPUT ;
    USE SIGNAL ;
    PORT
      LAYER M4 ;
        RECT  21.516 4.272 21.6 4.296 ;
    END
  END o[5]
  PIN o[60]
    DIRECTION OUTPUT ;
    USE SIGNAL ;
    PORT
      LAYER M4 ;
        RECT  21.516 12.624 21.6 12.648 ;
    END
  END o[60]
  PIN o[61]
    DIRECTION OUTPUT ;
    USE SIGNAL ;
    PORT
      LAYER M4 ;
        RECT  21.516 12.72 21.6 12.744 ;
    END
  END o[61]
  PIN o[62]
    DIRECTION OUTPUT ;
    USE SIGNAL ;
    PORT
      LAYER M4 ;
        RECT  21.516 12.816 21.6 12.84 ;
    END
  END o[62]
  PIN o[63]
    DIRECTION OUTPUT ;
    USE SIGNAL ;
    PORT
      LAYER M4 ;
        RECT  21.516 12.912 21.6 12.936 ;
    END
  END o[63]
  PIN o[64]
    DIRECTION OUTPUT ;
    USE SIGNAL ;
    PORT
      LAYER M4 ;
        RECT  21.516 26.064 21.6 26.088 ;
    END
  END o[64]
  PIN o[65]
    DIRECTION OUTPUT ;
    USE SIGNAL ;
    PORT
      LAYER M4 ;
        RECT  21.516 26.16 21.6 26.184 ;
    END
  END o[65]
  PIN o[66]
    DIRECTION OUTPUT ;
    USE SIGNAL ;
    PORT
      LAYER M4 ;
        RECT  21.516 26.256 21.6 26.28 ;
    END
  END o[66]
  PIN o[67]
    DIRECTION OUTPUT ;
    USE SIGNAL ;
    PORT
      LAYER M4 ;
        RECT  21.516 26.352 21.6 26.376 ;
    END
  END o[67]
  PIN o[68]
    DIRECTION OUTPUT ;
    USE SIGNAL ;
    PORT
      LAYER M4 ;
        RECT  21.516 26.448 21.6 26.472 ;
    END
  END o[68]
  PIN o[69]
    DIRECTION OUTPUT ;
    USE SIGNAL ;
    PORT
      LAYER M4 ;
        RECT  21.516 26.544 21.6 26.568 ;
    END
  END o[69]
  PIN o[6]
    DIRECTION OUTPUT ;
    USE SIGNAL ;
    PORT
      LAYER M4 ;
        RECT  21.516 4.368 21.6 4.392 ;
    END
  END o[6]
  PIN o[70]
    DIRECTION OUTPUT ;
    USE SIGNAL ;
    PORT
      LAYER M4 ;
        RECT  21.516 26.64 21.6 26.664 ;
    END
  END o[70]
  PIN o[71]
    DIRECTION OUTPUT ;
    USE SIGNAL ;
    PORT
      LAYER M4 ;
        RECT  21.516 26.736 21.6 26.76 ;
    END
  END o[71]
  PIN o[72]
    DIRECTION OUTPUT ;
    USE SIGNAL ;
    PORT
      LAYER M4 ;
        RECT  21.516 26.832 21.6 26.856 ;
    END
  END o[72]
  PIN o[73]
    DIRECTION OUTPUT ;
    USE SIGNAL ;
    PORT
      LAYER M4 ;
        RECT  21.516 26.928 21.6 26.952 ;
    END
  END o[73]
  PIN o[74]
    DIRECTION OUTPUT ;
    USE SIGNAL ;
    PORT
      LAYER M4 ;
        RECT  21.516 27.024 21.6 27.048 ;
    END
  END o[74]
  PIN o[75]
    DIRECTION OUTPUT ;
    USE SIGNAL ;
    PORT
      LAYER M4 ;
        RECT  21.516 27.12 21.6 27.144 ;
    END
  END o[75]
  PIN o[76]
    DIRECTION OUTPUT ;
    USE SIGNAL ;
    PORT
      LAYER M4 ;
        RECT  21.516 27.216 21.6 27.24 ;
    END
  END o[76]
  PIN o[77]
    DIRECTION OUTPUT ;
    USE SIGNAL ;
    PORT
      LAYER M4 ;
        RECT  21.516 27.312 21.6 27.336 ;
    END
  END o[77]
  PIN o[78]
    DIRECTION OUTPUT ;
    USE SIGNAL ;
    PORT
      LAYER M4 ;
        RECT  21.516 27.408 21.6 27.432 ;
    END
  END o[78]
  PIN o[79]
    DIRECTION OUTPUT ;
    USE SIGNAL ;
    PORT
      LAYER M4 ;
        RECT  21.516 27.504 21.6 27.528 ;
    END
  END o[79]
  PIN o[7]
    DIRECTION OUTPUT ;
    USE SIGNAL ;
    PORT
      LAYER M4 ;
        RECT  21.516 4.464 21.6 4.488 ;
    END
  END o[7]
  PIN o[80]
    DIRECTION OUTPUT ;
    USE SIGNAL ;
    PORT
      LAYER M4 ;
        RECT  21.516 27.6 21.6 27.624 ;
    END
  END o[80]
  PIN o[81]
    DIRECTION OUTPUT ;
    USE SIGNAL ;
    PORT
      LAYER M4 ;
        RECT  21.516 27.696 21.6 27.72 ;
    END
  END o[81]
  PIN o[82]
    DIRECTION OUTPUT ;
    USE SIGNAL ;
    PORT
      LAYER M4 ;
        RECT  21.516 27.792 21.6 27.816 ;
    END
  END o[82]
  PIN o[83]
    DIRECTION OUTPUT ;
    USE SIGNAL ;
    PORT
      LAYER M4 ;
        RECT  21.516 27.888 21.6 27.912 ;
    END
  END o[83]
  PIN o[84]
    DIRECTION OUTPUT ;
    USE SIGNAL ;
    PORT
      LAYER M4 ;
        RECT  21.516 27.984 21.6 28.008 ;
    END
  END o[84]
  PIN o[85]
    DIRECTION OUTPUT ;
    USE SIGNAL ;
    PORT
      LAYER M4 ;
        RECT  21.516 28.08 21.6 28.104 ;
    END
  END o[85]
  PIN o[86]
    DIRECTION OUTPUT ;
    USE SIGNAL ;
    PORT
      LAYER M4 ;
        RECT  21.516 28.176 21.6 28.2 ;
    END
  END o[86]
  PIN o[87]
    DIRECTION OUTPUT ;
    USE SIGNAL ;
    PORT
      LAYER M4 ;
        RECT  21.516 28.272 21.6 28.296 ;
    END
  END o[87]
  PIN o[88]
    DIRECTION OUTPUT ;
    USE SIGNAL ;
    PORT
      LAYER M4 ;
        RECT  21.516 28.368 21.6 28.392 ;
    END
  END o[88]
  PIN o[89]
    DIRECTION OUTPUT ;
    USE SIGNAL ;
    PORT
      LAYER M4 ;
        RECT  21.516 28.464 21.6 28.488 ;
    END
  END o[89]
  PIN o[8]
    DIRECTION OUTPUT ;
    USE SIGNAL ;
    PORT
      LAYER M4 ;
        RECT  21.516 4.56 21.6 4.584 ;
    END
  END o[8]
  PIN o[90]
    DIRECTION OUTPUT ;
    USE SIGNAL ;
    PORT
      LAYER M4 ;
        RECT  21.516 28.56 21.6 28.584 ;
    END
  END o[90]
  PIN o[91]
    DIRECTION OUTPUT ;
    USE SIGNAL ;
    PORT
      LAYER M4 ;
        RECT  21.516 28.656 21.6 28.68 ;
    END
  END o[91]
  PIN o[92]
    DIRECTION OUTPUT ;
    USE SIGNAL ;
    PORT
      LAYER M4 ;
        RECT  21.516 28.752 21.6 28.776 ;
    END
  END o[92]
  PIN o[93]
    DIRECTION OUTPUT ;
    USE SIGNAL ;
    PORT
      LAYER M4 ;
        RECT  21.516 28.848 21.6 28.872 ;
    END
  END o[93]
  PIN o[94]
    DIRECTION OUTPUT ;
    USE SIGNAL ;
    PORT
      LAYER M4 ;
        RECT  21.516 28.944 21.6 28.968 ;
    END
  END o[94]
  PIN o[95]
    DIRECTION OUTPUT ;
    USE SIGNAL ;
    PORT
      LAYER M4 ;
        RECT  21.516 29.04 21.6 29.064 ;
    END
  END o[95]
  PIN o[96]
    DIRECTION OUTPUT ;
    USE SIGNAL ;
    PORT
      LAYER M4 ;
        RECT  21.516 13.008 21.6 13.032 ;
    END
  END o[96]
  PIN o[97]
    DIRECTION OUTPUT ;
    USE SIGNAL ;
    PORT
      LAYER M4 ;
        RECT  21.516 13.104 21.6 13.128 ;
    END
  END o[97]
  PIN o[98]
    DIRECTION OUTPUT ;
    USE SIGNAL ;
    PORT
      LAYER M4 ;
        RECT  21.516 13.2 21.6 13.224 ;
    END
  END o[98]
  PIN o[99]
    DIRECTION OUTPUT ;
    USE SIGNAL ;
    PORT
      LAYER M4 ;
        RECT  21.516 13.296 21.6 13.32 ;
    END
  END o[99]
  PIN o[9]
    DIRECTION OUTPUT ;
    USE SIGNAL ;
    PORT
      LAYER M4 ;
        RECT  21.516 4.656 21.6 4.68 ;
    END
  END o[9]
  PIN rs
    DIRECTION INPUT ;
    USE SIGNAL ;
    PORT
      LAYER M5 ;
        RECT  12.912 0 12.936 0.084 ;
    END
  END rs
  PIN VDD
    DIRECTION INOUT ;
    USE POWER ;
    PORT
      LAYER M5 ;
        RECT  18.792 2.151 18.912 32.409 ;
        RECT  16.092 2.151 16.212 32.409 ;
        RECT  13.392 2.151 13.512 32.409 ;
        RECT  10.692 2.151 10.812 32.409 ;
        RECT  7.992 2.151 8.112 32.409 ;
        RECT  5.292 2.151 5.412 32.409 ;
        RECT  2.592 2.151 2.712 32.409 ;
    END
  END VDD
  PIN VSS
    DIRECTION INOUT ;
    USE GROUND ;
    PORT
      LAYER M5 ;
        RECT  18.6 2.137 18.72 32.423 ;
        RECT  15.9 2.137 16.02 32.423 ;
        RECT  13.2 2.137 13.32 32.423 ;
        RECT  10.5 2.137 10.62 32.423 ;
        RECT  7.8 2.137 7.92 32.423 ;
        RECT  5.1 2.137 5.22 32.423 ;
        RECT  2.4 2.137 2.52 32.423 ;
    END
  END VSS
  # OT_OBS_CLOSED layer=M5 d_um=1.536 added=48
  OBS
    LAYER RVTN ;
     RECT  2.16 2.16 19.44 2.295 ;
     RECT  2.16 2.565 19.44 2.835 ;
     RECT  2.16 3.105 19.44 3.375 ;
     RECT  2.16 3.645 19.44 3.915 ;
     RECT  2.16 4.185 19.44 4.455 ;
     RECT  2.16 4.725 19.44 4.995 ;
     RECT  2.16 5.265 19.44 5.535 ;
     RECT  2.16 5.805 19.44 6.075 ;
     RECT  2.16 6.345 19.44 6.615 ;
     RECT  2.16 6.885 19.44 7.155 ;
     RECT  2.16 7.425 19.44 7.695 ;
     RECT  2.16 7.965 19.44 8.235 ;
     RECT  2.16 8.505 19.44 8.775 ;
     RECT  2.16 9.045 19.44 9.315 ;
     RECT  2.16 9.585 19.44 9.855 ;
     RECT  2.16 10.125 19.44 10.395 ;
     RECT  2.16 10.665 19.44 10.935 ;
     RECT  2.16 11.205 19.44 11.475 ;
     RECT  2.16 11.745 19.44 12.015 ;
     RECT  2.16 12.285 19.44 12.555 ;
     RECT  2.16 12.825 19.44 13.095 ;
     RECT  2.16 13.365 19.44 13.635 ;
     RECT  2.16 13.905 19.44 14.175 ;
     RECT  2.16 14.445 19.44 14.715 ;
     RECT  2.16 14.985 19.44 15.255 ;
     RECT  2.16 15.525 19.44 15.795 ;
     RECT  2.16 16.065 19.44 16.335 ;
     RECT  2.16 16.605 19.44 16.875 ;
     RECT  2.16 17.145 19.44 17.415 ;
     RECT  2.16 17.685 19.44 17.955 ;
     RECT  2.16 18.225 19.44 18.495 ;
     RECT  2.16 18.765 19.44 19.035 ;
     RECT  2.16 19.305 19.44 19.575 ;
     RECT  2.16 19.845 19.44 20.115 ;
     RECT  2.16 20.385 19.44 20.655 ;
     RECT  2.16 20.925 19.44 21.195 ;
     RECT  2.16 21.465 19.44 21.735 ;
     RECT  2.16 22.005 19.44 22.275 ;
     RECT  2.16 22.545 19.44 22.815 ;
     RECT  2.16 23.085 19.44 23.355 ;
     RECT  2.16 23.625 19.44 23.895 ;
     RECT  2.16 24.165 19.44 24.435 ;
     RECT  2.16 24.705 19.44 24.975 ;
     RECT  2.16 25.245 19.44 25.515 ;
     RECT  2.16 25.785 19.44 26.055 ;
     RECT  2.16 26.325 19.44 26.595 ;
     RECT  2.16 26.865 19.44 27.135 ;
     RECT  2.16 27.405 19.44 27.675 ;
     RECT  2.16 27.945 19.44 28.215 ;
     RECT  2.16 28.485 19.44 28.755 ;
     RECT  2.16 29.025 19.44 29.295 ;
     RECT  2.16 29.565 19.44 29.835 ;
     RECT  2.16 30.105 19.44 30.375 ;
     RECT  2.16 30.645 19.44 30.915 ;
     RECT  2.16 31.185 19.44 31.455 ;
     RECT  2.16 31.725 19.44 31.995 ;
     RECT  2.16 32.265 19.44 32.4 ;
    LAYER RVTP ;
     RECT  2.16 2.295 19.44 2.565 ;
     RECT  2.16 2.835 19.44 3.105 ;
     RECT  2.16 3.375 19.44 3.645 ;
     RECT  2.16 3.915 19.44 4.185 ;
     RECT  2.16 4.455 19.44 4.725 ;
     RECT  2.16 4.995 19.44 5.265 ;
     RECT  2.16 5.535 19.44 5.805 ;
     RECT  2.16 6.075 19.44 6.345 ;
     RECT  2.16 6.615 19.44 6.885 ;
     RECT  2.16 7.155 19.44 7.425 ;
     RECT  2.16 7.695 19.44 7.965 ;
     RECT  2.16 8.235 19.44 8.505 ;
     RECT  2.16 8.775 19.44 9.045 ;
     RECT  2.16 9.315 19.44 9.585 ;
     RECT  2.16 9.855 19.44 10.125 ;
     RECT  2.16 10.395 19.44 10.665 ;
     RECT  2.16 10.935 19.44 11.205 ;
     RECT  2.16 11.475 19.44 11.745 ;
     RECT  2.16 12.015 19.44 12.285 ;
     RECT  2.16 12.555 19.44 12.825 ;
     RECT  2.16 13.095 19.44 13.365 ;
     RECT  2.16 13.635 19.44 13.905 ;
     RECT  2.16 14.175 19.44 14.445 ;
     RECT  2.16 14.715 19.44 14.985 ;
     RECT  2.16 15.255 19.44 15.525 ;
     RECT  2.16 15.795 19.44 16.065 ;
     RECT  2.16 16.335 19.44 16.605 ;
     RECT  2.16 16.875 19.44 17.145 ;
     RECT  2.16 17.415 19.44 17.685 ;
     RECT  2.16 17.955 19.44 18.225 ;
     RECT  2.16 18.495 19.44 18.765 ;
     RECT  2.16 19.035 19.44 19.305 ;
     RECT  2.16 19.575 19.44 19.845 ;
     RECT  2.16 20.115 19.44 20.385 ;
     RECT  2.16 20.655 19.44 20.925 ;
     RECT  2.16 21.195 19.44 21.465 ;
     RECT  2.16 21.735 19.44 22.005 ;
     RECT  2.16 22.275 19.44 22.545 ;
     RECT  2.16 22.815 19.44 23.085 ;
     RECT  2.16 23.355 19.44 23.625 ;
     RECT  2.16 23.895 19.44 24.165 ;
     RECT  2.16 24.435 19.44 24.705 ;
     RECT  2.16 24.975 19.44 25.245 ;
     RECT  2.16 25.515 19.44 25.785 ;
     RECT  2.16 26.055 19.44 26.325 ;
     RECT  2.16 26.595 19.44 26.865 ;
     RECT  2.16 27.135 19.44 27.405 ;
     RECT  2.16 27.675 19.44 27.945 ;
     RECT  2.16 28.215 19.44 28.485 ;
     RECT  2.16 28.755 19.44 29.025 ;
     RECT  2.16 29.295 19.44 29.565 ;
     RECT  2.16 29.835 19.44 30.105 ;
     RECT  2.16 30.375 19.44 30.645 ;
     RECT  2.16 30.915 19.44 31.185 ;
     RECT  2.16 31.455 19.44 31.725 ;
     RECT  2.16 31.995 19.44 32.265 ;
    LAYER M1 ;
     RECT  2.16 2.151 19.44 32.409 ;
    LAYER M2 ;
     RECT  0.031 26.298 0.067 26.316 ;
     RECT  0.031 18.036 0.103 18.054 ;
     RECT  0.067 20.7 0.103 20.718 ;
     RECT  0.067 26.298 0.103 26.82 ;
     RECT  0.031 23.94 0.131 23.958 ;
     RECT  0.031 30.816 0.131 30.834 ;
     RECT  0.103 3.15 0.139 3.168 ;
     RECT  0.103 9.36 0.139 9.378 ;
     RECT  0.103 10.368 0.139 10.386 ;
     RECT  0.103 15.57 0.139 15.588 ;
     RECT  0.103 26.298 0.139 26.928 ;
     RECT  0.139 3.15 0.175 3.402 ;
     RECT  0.103 22.212 0.175 22.77 ;
     RECT  0.139 14.76 0.247 15.588 ;
     RECT  0.175 21.942 0.247 22.77 ;
     RECT  0.211 29.88 0.247 29.898 ;
     RECT  0.103 16.956 0.283 19.8 ;
     RECT  0.103 20.7 0.283 20.988 ;
     RECT  0.211 23.634 0.283 23.688 ;
     RECT  0.247 21.942 0.319 22.806 ;
     RECT  0.283 23.562 0.319 23.688 ;
     RECT  0.103 28.8 0.355 28.818 ;
     RECT  0.319 21.942 0.391 23.688 ;
     RECT  0.139 26.298 0.427 27.36 ;
     RECT  0.355 28.458 0.427 28.818 ;
     RECT  0.175 3.15 0.499 3.978 ;
     RECT  0.103 4.734 0.499 4.752 ;
     RECT  0.247 14.49 0.499 15.588 ;
     RECT  0.391 21.816 0.527 23.688 ;
     RECT  0.499 3.15 0.535 4.752 ;
     RECT  0.103 6.012 0.535 6.03 ;
     RECT  0.499 14.49 0.535 16.092 ;
     RECT  0.283 16.956 0.535 20.988 ;
     RECT  0.535 14.49 1.147 20.988 ;
     RECT  0.535 24.48 1.147 24.498 ;
     RECT  1.147 14.382 1.543 20.988 ;
     RECT  0.247 29.88 1.615 30.402 ;
     RECT  0.427 26.298 1.651 28.818 ;
     RECT  1.615 29.574 1.651 30.402 ;
     RECT  1.147 24.48 1.723 24.66 ;
     RECT  1.723 24.48 1.759 24.93 ;
     RECT  1.759 24.48 1.795 25.2 ;
     RECT  1.543 14.22 2.119 20.988 ;
     RECT  0.527 21.816 2.119 22.77 ;
     RECT  0.535 3.15 2.16 4.788 ;
     RECT  0.535 5.58 2.16 6.03 ;
     RECT  0.211 7.092 2.16 7.11 ;
     RECT  0.139 9.36 2.16 10.386 ;
     RECT  0.535 11.25 2.16 11.268 ;
     RECT  2.119 14.22 2.16 22.77 ;
     RECT  0.527 23.67 2.16 23.688 ;
     RECT  1.795 24.48 2.16 25.47 ;
     RECT  1.651 26.298 2.16 30.402 ;
     RECT  0.535 31.194 2.16 31.212 ;
     RECT  2.16 2.151 2.767 32.409 ;
     RECT  2.767 2.151 3.019 32.454 ;
     RECT  3.019 2.106 3.839 32.454 ;
     RECT  3.839 2.106 4.099 32.409 ;
     RECT  4.099 2.034 6.547 32.409 ;
     RECT  6.547 1.998 7.987 32.409 ;
     RECT  7.987 1.926 12.055 32.409 ;
     RECT  12.055 1.881 12.911 32.409 ;
     RECT  12.911 1.926 13.055 32.409 ;
     RECT  13.055 1.962 15.331 32.409 ;
     RECT  15.331 1.926 15.763 32.409 ;
     RECT  15.763 1.881 17.591 32.409 ;
     RECT  17.591 1.926 18.203 32.409 ;
     RECT  18.203 1.998 18.239 32.409 ;
     RECT  18.239 2.106 19.44 32.409 ;
     RECT  19.44 2.106 19.931 32.364 ;
     RECT  19.931 2.106 19.967 32.292 ;
     RECT  19.967 2.268 20.219 32.292 ;
     RECT  20.219 20.556 20.399 32.184 ;
     RECT  20.219 2.268 20.435 19.764 ;
     RECT  20.399 20.556 20.435 20.844 ;
     RECT  20.435 2.268 20.471 14.859 ;
     RECT  20.435 15.606 20.471 19.764 ;
     RECT  20.435 20.556 20.471 20.718 ;
     RECT  20.471 2.268 20.507 10.314 ;
     RECT  20.471 11.214 20.507 14.859 ;
     RECT  20.471 15.606 20.507 18.684 ;
     RECT  20.471 19.656 20.507 19.764 ;
     RECT  20.471 20.7 20.507 20.718 ;
     RECT  20.399 21.906 20.507 32.184 ;
     RECT  20.507 2.268 20.543 5.868 ;
     RECT  20.507 6.624 20.543 9.072 ;
     RECT  20.507 11.214 20.543 11.538 ;
     RECT  20.507 13.41 20.543 14.859 ;
     RECT  20.507 15.606 20.543 18.099 ;
     RECT  20.507 19.656 20.543 19.674 ;
     RECT  20.507 22.626 20.543 25.272 ;
     RECT  20.507 26.334 20.543 28.854 ;
     RECT  20.507 29.844 20.543 30.132 ;
     RECT  20.543 4.896 20.579 5.868 ;
     RECT  20.543 6.894 20.579 8.694 ;
     RECT  20.507 9.936 20.579 10.314 ;
     RECT  20.543 13.644 20.579 14.859 ;
     RECT  20.543 15.606 20.579 15.624 ;
     RECT  20.543 22.788 20.579 25.272 ;
     RECT  20.579 9.981 20.615 10.314 ;
     RECT  20.543 11.214 20.615 11.502 ;
     RECT  20.579 14.841 20.615 14.859 ;
     RECT  20.543 26.496 20.615 28.854 ;
     RECT  20.615 11.331 20.651 11.394 ;
     RECT  20.543 2.268 21.407 2.286 ;
     RECT  20.579 4.896 21.407 5.562 ;
     RECT  20.543 3.078 21.415 3.672 ;
     RECT  20.615 10.206 21.443 10.314 ;
     RECT  20.579 7.596 21.479 8.694 ;
     RECT  21.443 10.296 21.479 10.314 ;
     RECT  20.507 12.294 21.479 12.582 ;
     RECT  20.579 23.166 21.479 25.272 ;
     RECT  20.615 26.676 21.479 28.854 ;
     RECT  21.415 2.466 21.515 3.834 ;
     RECT  21.407 5.166 21.515 5.562 ;
     RECT  21.479 8.316 21.515 8.694 ;
     RECT  20.651 11.376 21.515 11.394 ;
     RECT  21.479 12.564 21.515 12.582 ;
     RECT  20.543 17.226 21.515 17.874 ;
     RECT  21.479 23.166 21.515 24.66 ;
     RECT  21.479 26.766 21.515 26.784 ;
     RECT  21.479 27.648 21.515 28.854 ;
     RECT  20.543 30.114 21.515 30.132 ;
     RECT  20.507 31.194 21.515 31.554 ;
     RECT  21.515 2.466 21.587 2.484 ;
     RECT  21.515 5.166 21.587 5.184 ;
    LAYER M3 ;
     RECT  19.44 0.715 19.458 0.811 ;
     RECT  19.368 0.811 19.458 1.003 ;
     RECT  21.492 0.907 21.51 1.195 ;
     RECT  19.368 1.003 19.674 1.387 ;
     RECT  19.224 1.387 19.674 1.483 ;
     RECT  19.152 1.483 19.674 1.675 ;
     RECT  20.484 1.291 20.502 1.675 ;
     RECT  12.888 0.571 12.906 1.921 ;
     RECT  15.768 1.876 15.786 1.921 ;
     RECT  17.568 1.876 17.586 1.921 ;
     RECT  18.324 1.099 18.342 1.921 ;
     RECT  15.336 1.921 15.786 1.957 ;
     RECT  14.616 1.957 15.786 1.993 ;
     RECT  12.06 1.876 12.078 2.029 ;
     RECT  12.888 1.921 13.05 2.029 ;
     RECT  6.552 1.993 6.57 2.065 ;
     RECT  12.06 2.029 13.05 2.065 ;
     RECT  14.616 1.993 16.074 2.065 ;
     RECT  10.836 1.957 10.854 2.093 ;
     RECT  4.104 2.029 4.122 2.101 ;
     RECT  6.552 2.065 7.002 2.101 ;
     RECT  14.616 2.065 16.686 2.101 ;
     RECT  17.568 1.921 18.342 2.101 ;
     RECT  19.152 1.675 20.502 2.101 ;
     RECT  3.024 2.101 3.042 2.143 ;
     RECT  7.992 1.921 8.01 2.143 ;
     RECT  5.115 2.143 5.205 2.191 ;
     RECT  2.415 2.143 3.042 2.227 ;
     RECT  12.06 2.065 13.77 2.227 ;
     RECT  14.544 2.101 16.686 2.227 ;
     RECT  6.444 2.101 7.002 2.251 ;
     RECT  2.304 2.227 3.042 2.263 ;
     RECT  3.924 2.101 4.122 2.263 ;
     RECT  12.06 2.227 16.686 2.263 ;
     RECT  21.456 1.195 21.51 2.263 ;
     RECT  6.3 2.251 7.002 2.293 ;
     RECT  6.228 2.293 7.002 2.296 ;
     RECT  7.815 2.143 8.01 2.296 ;
     RECT  5.115 2.191 5.454 2.335 ;
     RECT  6.228 2.296 8.01 2.335 ;
     RECT  12.06 2.263 16.794 2.335 ;
     RECT  17.568 2.101 20.502 2.335 ;
     RECT  10.515 2.143 10.797 2.371 ;
     RECT  5.115 2.335 8.01 2.413 ;
     RECT  21.384 2.263 21.51 2.461 ;
     RECT  5.115 2.413 8.097 2.497 ;
     RECT  12.06 2.335 20.502 2.539 ;
     RECT  9.468 2.533 9.558 2.569 ;
     RECT  10.296 2.371 10.797 2.569 ;
     RECT  2.304 2.263 4.122 2.587 ;
     RECT  4.896 2.497 8.73 2.587 ;
     RECT  2.304 2.587 8.73 2.605 ;
     RECT  9.468 2.569 10.797 2.605 ;
     RECT  12.06 2.539 20.538 2.605 ;
     RECT  11.988 2.605 20.538 2.641 ;
     RECT  21.384 2.461 21.582 2.861 ;
     RECT  2.304 2.605 10.797 2.875 ;
     RECT  2.304 2.875 10.926 3.001 ;
     RECT  2.304 3.001 11.034 3.037 ;
     RECT  11.952 2.641 20.538 3.037 ;
     RECT  0.108 3.145 0.126 3.379 ;
     RECT  2.304 3.037 20.538 3.403 ;
     RECT  2.304 3.403 20.574 3.547 ;
     RECT  21.456 2.861 21.582 3.595 ;
     RECT  0.108 3.379 0.162 3.955 ;
     RECT  0.108 3.955 0.198 4.225 ;
     RECT  0.108 4.225 0.522 4.765 ;
     RECT  21.384 3.595 21.582 4.919 ;
     RECT  21.456 4.919 21.582 5.189 ;
     RECT  2.268 3.547 20.574 5.225 ;
     RECT  21.456 5.189 21.51 5.567 ;
     RECT  2.304 5.225 20.574 5.873 ;
     RECT  0.108 4.765 0.558 6.029 ;
     RECT  0.108 6.029 0.126 6.509 ;
     RECT  2.304 5.873 20.502 6.619 ;
     RECT  2.304 6.619 20.538 6.889 ;
     RECT  2.304 6.889 20.574 7.051 ;
     RECT  2.268 7.051 20.574 7.115 ;
     RECT  2.268 7.115 19.062 7.277 ;
     RECT  19.8 7.115 20.574 7.469 ;
     RECT  21.456 5.567 21.474 7.618 ;
     RECT  21.456 7.618 21.51 7.619 ;
     RECT  0.216 7.087 0.234 7.819 ;
     RECT  2.304 7.277 19.062 7.925 ;
     RECT  0.144 7.819 0.234 7.949 ;
     RECT  0.144 7.949 0.162 7.997 ;
     RECT  2.304 7.925 8.694 8.107 ;
     RECT  2.268 8.107 8.694 8.303 ;
     RECT  19.8 7.469 20.502 8.303 ;
     RECT  2.304 8.303 8.694 8.465 ;
     RECT  7.776 8.465 8.694 8.477 ;
     RECT  19.872 8.303 20.502 8.491 ;
     RECT  2.304 8.465 6.894 8.735 ;
     RECT  9.576 7.925 19.062 8.779 ;
     RECT  2.376 8.735 2.862 8.969 ;
     RECT  7.776 8.477 8.097 9.211 ;
     RECT  7.02 9.211 8.097 9.319 ;
     RECT  9.144 8.779 19.062 9.319 ;
     RECT  7.02 9.319 19.062 9.451 ;
     RECT  19.872 8.491 20.538 9.451 ;
     RECT  7.02 9.451 20.538 9.589 ;
     RECT  0.108 9.355 0.126 9.625 ;
     RECT  6.804 9.589 20.538 9.751 ;
     RECT  2.376 8.969 2.79 9.787 ;
     RECT  3.672 8.735 5.397 9.859 ;
     RECT  6.12 9.751 20.538 9.859 ;
     RECT  2.34 9.787 2.79 9.931 ;
     RECT  3.672 9.859 20.538 9.931 ;
     RECT  21.492 7.619 21.51 9.931 ;
     RECT  3.672 9.931 20.574 9.976 ;
     RECT  2.34 9.931 2.826 10.129 ;
     RECT  2.34 10.129 2.862 10.165 ;
     RECT  21.456 9.931 21.51 10.201 ;
     RECT  21.42 10.201 21.51 10.253 ;
     RECT  21.456 10.253 21.51 10.319 ;
     RECT  3.672 9.976 20.61 10.435 ;
     RECT  2.304 10.165 2.862 10.471 ;
     RECT  3.636 10.435 20.61 10.471 ;
     RECT  2.304 10.471 20.61 10.637 ;
     RECT  2.304 10.637 19.494 10.795 ;
     RECT  20.34 10.637 20.61 10.829 ;
     RECT  0.108 9.625 0.198 11.083 ;
     RECT  2.268 10.795 19.494 11.129 ;
     RECT  0.108 11.083 0.342 11.213 ;
     RECT  20.412 10.829 20.61 11.326 ;
     RECT  21.492 10.319 21.51 11.399 ;
     RECT  2.268 11.129 9.162 11.435 ;
     RECT  9.9 11.129 19.494 12.043 ;
     RECT  20.412 11.326 20.646 12.043 ;
     RECT  2.304 11.435 9.162 12.055 ;
     RECT  9.9 12.043 20.646 12.055 ;
     RECT  2.304 12.055 20.646 12.173 ;
     RECT  0.54 11.245 0.558 12.269 ;
     RECT  21.456 12.289 21.474 12.427 ;
     RECT  21.456 12.427 21.51 12.587 ;
     RECT  21.456 12.587 21.474 12.845 ;
     RECT  2.304 12.173 20.574 12.857 ;
     RECT  2.304 12.857 19.422 13.003 ;
     RECT  2.268 13.003 19.422 13.387 ;
     RECT  20.196 12.857 20.574 13.469 ;
     RECT  1.98 13.387 19.422 13.909 ;
     RECT  1.152 12.427 1.17 13.963 ;
     RECT  1.98 13.909 19.458 13.963 ;
     RECT  1.152 13.963 19.458 14.189 ;
     RECT  20.412 13.469 20.574 14.347 ;
     RECT  1.152 14.189 19.422 14.405 ;
     RECT  21.42 14.251 21.438 14.429 ;
     RECT  0.108 14.251 0.126 14.485 ;
     RECT  0.108 14.485 0.27 14.669 ;
     RECT  20.196 14.347 20.574 14.836 ;
     RECT  1.404 14.405 19.422 14.923 ;
     RECT  20.196 14.836 20.61 14.923 ;
     RECT  1.404 14.923 20.61 15.341 ;
     RECT  0.144 14.669 0.27 15.565 ;
     RECT  1.404 15.341 20.574 15.725 ;
     RECT  1.404 15.725 20.538 15.827 ;
     RECT  0.108 15.565 0.27 15.835 ;
     RECT  19.908 15.827 20.538 16.747 ;
     RECT  1.404 15.827 19.134 16.871 ;
     RECT  1.98 16.871 19.134 16.951 ;
     RECT  19.872 16.747 20.538 16.951 ;
     RECT  1.98 16.951 20.538 17.141 ;
     RECT  0.108 15.835 0.558 17.165 ;
     RECT  19.908 17.141 20.538 17.165 ;
     RECT  0.108 17.165 0.342 17.453 ;
     RECT  21.492 16.075 21.51 17.879 ;
     RECT  1.98 17.141 19.134 17.959 ;
     RECT  1.404 17.959 19.134 17.995 ;
     RECT  19.908 17.165 20.502 17.995 ;
     RECT  0.108 17.453 0.126 18.031 ;
     RECT  1.404 17.995 20.502 18.076 ;
     RECT  1.404 18.076 20.538 18.125 ;
     RECT  0.036 18.031 0.126 18.283 ;
     RECT  0.036 18.283 0.162 18.301 ;
     RECT  0.036 18.301 0.198 18.805 ;
     RECT  1.404 18.125 20.502 18.959 ;
     RECT  21.42 18.043 21.438 19.037 ;
     RECT  0.036 18.805 0.234 19.147 ;
     RECT  20.412 18.959 20.502 19.229 ;
     RECT  20.484 19.229 20.502 19.651 ;
     RECT  1.404 18.959 19.674 20.011 ;
     RECT  20.484 19.651 20.538 20.011 ;
     RECT  0.036 19.147 0.342 20.083 ;
     RECT  1.404 20.011 20.538 20.237 ;
     RECT  1.404 20.237 20.502 20.957 ;
     RECT  1.404 20.957 19.422 21.005 ;
     RECT  1.404 21.005 19.386 21.569 ;
     RECT  1.404 21.569 19.206 21.659 ;
     RECT  1.404 21.659 18.954 21.965 ;
     RECT  1.404 21.965 8.226 22.235 ;
     RECT  9.108 21.965 18.954 22.235 ;
     RECT  12.24 22.235 18.954 22.349 ;
     RECT  0.036 20.083 0.45 22.411 ;
     RECT  1.404 22.235 8.097 22.411 ;
     RECT  13.215 22.349 18.954 22.549 ;
     RECT  20.232 20.957 20.502 22.621 ;
     RECT  13.215 22.549 19.278 22.747 ;
     RECT  20.232 22.621 20.538 22.747 ;
     RECT  13.215 22.747 20.538 22.783 ;
     RECT  21.42 22.795 21.438 22.987 ;
     RECT  9.108 22.235 9.702 23.089 ;
     RECT  21.312 22.987 21.438 23.117 ;
     RECT  12.24 22.349 12.258 23.125 ;
     RECT  13.215 22.783 20.574 23.125 ;
     RECT  0.036 22.411 8.097 23.251 ;
     RECT  8.964 23.089 9.702 23.251 ;
     RECT  12.24 23.125 20.574 23.275 ;
     RECT  12.06 23.275 20.574 23.309 ;
     RECT  0.036 23.251 9.738 23.431 ;
     RECT  10.515 22.235 10.926 23.431 ;
     RECT  0.036 23.431 10.926 23.593 ;
     RECT  12.06 23.309 20.538 23.593 ;
     RECT  0.036 23.593 20.538 23.963 ;
     RECT  0.072 23.963 20.538 24.365 ;
     RECT  0.072 24.365 20.214 24.467 ;
     RECT  0.072 24.467 19.998 24.503 ;
     RECT  0.072 24.503 5.397 24.665 ;
     RECT  6.12 24.503 19.998 24.935 ;
     RECT  6.12 24.935 11.394 24.971 ;
     RECT  12.456 24.935 19.998 25.205 ;
     RECT  1.404 24.665 5.397 25.229 ;
     RECT  21.492 23.161 21.51 25.249 ;
     RECT  6.3 24.971 11.394 25.313 ;
     RECT  1.404 25.229 3.978 25.421 ;
     RECT  19.944 25.205 19.998 25.421 ;
     RECT  6.408 25.313 11.394 25.439 ;
     RECT  6.444 25.439 11.394 25.511 ;
     RECT  6.588 25.511 11.394 25.583 ;
     RECT  6.588 25.583 6.894 25.619 ;
     RECT  1.44 25.421 3.978 25.709 ;
     RECT  12.456 25.205 19.206 25.825 ;
     RECT  4.716 25.229 5.397 25.861 ;
     RECT  7.668 25.583 11.394 25.861 ;
     RECT  12.168 25.825 19.206 25.861 ;
     RECT  20.484 25.483 20.502 25.867 ;
     RECT  7.668 25.861 19.206 26.051 ;
     RECT  12.348 26.051 19.206 26.059 ;
     RECT  2.304 25.709 3.978 26.087 ;
     RECT  2.34 26.087 3.978 26.221 ;
     RECT  4.716 25.861 5.49 26.221 ;
     RECT  7.668 26.051 11.61 26.249 ;
     RECT  12.348 26.059 19.422 26.251 ;
     RECT  20.484 25.867 20.538 26.251 ;
     RECT  0.072 24.665 0.558 26.293 ;
     RECT  6.876 25.619 6.894 26.365 ;
     RECT  7.668 26.249 11.07 26.429 ;
     RECT  1.44 25.709 1.458 26.477 ;
     RECT  12.348 26.251 20.538 26.491 ;
     RECT  2.34 26.221 5.49 26.599 ;
     RECT  6.408 26.365 6.894 26.599 ;
     RECT  2.34 26.599 6.894 26.827 ;
     RECT  2.304 26.827 6.894 26.905 ;
     RECT  7.668 26.429 10.998 26.905 ;
     RECT  12.348 26.491 20.61 27.031 ;
     RECT  2.304 26.905 10.998 27.175 ;
     RECT  11.808 27.031 20.61 27.175 ;
     RECT  2.304 27.175 20.61 27.329 ;
     RECT  2.304 27.329 11.682 27.337 ;
     RECT  2.232 27.337 11.682 27.341 ;
     RECT  12.492 27.329 20.61 27.365 ;
     RECT  2.232 27.341 11.538 27.437 ;
     RECT  21.456 25.249 21.51 27.533 ;
     RECT  12.528 27.365 20.61 27.821 ;
     RECT  0.036 26.293 0.558 28.013 ;
     RECT  0.036 28.013 0.522 28.109 ;
     RECT  2.304 27.437 11.538 28.111 ;
     RECT  12.528 27.821 20.538 28.111 ;
     RECT  0.036 28.109 0.486 28.205 ;
     RECT  2.304 28.111 20.538 28.493 ;
     RECT  0.036 28.205 0.45 28.685 ;
     RECT  10.476 28.493 20.538 29.069 ;
     RECT  1.404 27.643 1.422 29.299 ;
     RECT  2.304 28.493 9.63 29.299 ;
     RECT  1.404 29.299 9.63 29.371 ;
     RECT  10.476 29.069 20.502 29.371 ;
     RECT  1.404 29.371 20.502 29.839 ;
     RECT  1.404 29.839 20.538 29.851 ;
     RECT  1.152 29.851 20.538 30.125 ;
     RECT  1.404 30.125 20.502 30.509 ;
     RECT  21.492 27.533 21.51 30.763 ;
     RECT  0.036 28.685 0.378 30.839 ;
     RECT  1.404 30.509 19.098 30.875 ;
     RECT  21.42 30.763 21.51 30.941 ;
     RECT  1.404 30.875 18.954 31.109 ;
     RECT  1.404 31.109 6.354 31.181 ;
     RECT  0.108 30.839 0.378 31.189 ;
     RECT  0.108 31.189 0.558 31.373 ;
     RECT  21.456 30.941 21.51 31.379 ;
     RECT  19.98 30.509 20.502 31.495 ;
     RECT  21.492 31.379 21.51 31.559 ;
     RECT  0.216 31.373 0.558 31.565 ;
     RECT  1.62 31.181 6.354 31.649 ;
     RECT  1.62 31.649 6.282 31.757 ;
     RECT  19.944 31.495 20.502 31.819 ;
     RECT  7.128 31.109 18.954 31.829 ;
     RECT  2.232 31.757 6.282 31.853 ;
     RECT  9.54 31.829 18.954 31.853 ;
     RECT  2.268 31.853 6.282 31.919 ;
     RECT  7.128 31.829 8.658 31.919 ;
     RECT  13.068 31.853 18.954 31.991 ;
     RECT  14.544 31.991 18.954 31.999 ;
     RECT  19.908 31.819 20.502 31.999 ;
     RECT  14.544 31.999 20.502 32.045 ;
     RECT  7.815 31.919 8.658 32.063 ;
     RECT  2.268 31.919 6.138 32.099 ;
     RECT  10.515 31.853 11.538 32.099 ;
     RECT  14.544 32.045 18.954 32.099 ;
     RECT  13.068 31.991 13.497 32.147 ;
     RECT  14.544 32.099 17.37 32.189 ;
     RECT  19.908 32.045 20.502 32.189 ;
     RECT  2.268 32.099 5.85 32.225 ;
     RECT  18.396 32.099 18.954 32.225 ;
     RECT  13.068 32.147 13.305 32.261 ;
     RECT  15.012 32.189 17.19 32.261 ;
     RECT  5.004 32.225 5.742 32.297 ;
     RECT  7.815 32.063 8.622 32.297 ;
     RECT  10.515 32.099 10.854 32.297 ;
     RECT  19.908 32.189 20.214 32.297 ;
     RECT  0.252 31.565 0.558 32.333 ;
     RECT  18.396 32.225 18.705 32.333 ;
     RECT  5.115 32.297 5.742 32.369 ;
     RECT  15.012 32.261 15.03 32.369 ;
     RECT  15.768 32.261 16.005 32.369 ;
     RECT  16.92 32.261 16.938 32.369 ;
     RECT  19.908 32.297 19.926 32.369 ;
     RECT  2.268 32.225 3.978 32.381 ;
     RECT  5.115 32.369 5.205 32.417 ;
     RECT  7.815 32.297 7.905 32.417 ;
     RECT  10.515 32.297 10.605 32.417 ;
     RECT  13.215 32.261 13.305 32.417 ;
     RECT  15.915 32.369 16.005 32.417 ;
     RECT  18.615 32.333 18.705 32.417 ;
     RECT  2.304 32.381 3.978 32.477 ;
     RECT  0.432 32.333 0.558 32.573 ;
     RECT  2.844 32.477 3.978 33.005 ;
     RECT  2.844 33.005 3.402 33.101 ;
     RECT  2.844 33.101 2.898 33.389 ;
     RECT  0.54 32.573 0.558 33.677 ;
     RECT  2.88 33.389 2.898 33.773 ;
    LAYER M4 ;
     RECT  0.06 2.352 0.133 8.424 ;
     RECT  0.06 10.032 0.137 33.768 ;
     RECT  0.133 2.256 0.229 8.424 ;
     RECT  0.229 2.256 2.293 8.568 ;
     RECT  2.293 2.256 2.408 8.76 ;
     RECT  0.137 10.128 2.408 33.768 ;
     RECT  2.408 2.148 2.512 33.768 ;
     RECT  2.512 2.352 2.585 33.768 ;
     RECT  2.585 2.418 2.704 33.768 ;
     RECT  2.704 26.544 2.909 33.768 ;
     RECT  2.909 26.544 3.413 33.096 ;
     RECT  2.704 2.832 3.443 8.664 ;
     RECT  3.443 3.312 3.805 8.664 ;
     RECT  2.704 11.184 3.805 25.512 ;
     RECT  3.413 26.544 3.805 33 ;
     RECT  3.805 11.184 3.989 33 ;
     RECT  3.989 11.184 4.019 32.232 ;
     RECT  3.805 3.312 4.417 9.336 ;
     RECT  4.019 11.184 4.885 25.224 ;
     RECT  4.885 10.8 5.029 25.224 ;
     RECT  4.417 2.592 5.108 9.336 ;
     RECT  5.029 10.32 5.108 25.224 ;
     RECT  4.019 26.544 5.108 32.232 ;
     RECT  5.108 2.148 5.212 32.412 ;
     RECT  5.212 2.256 5.404 32.142 ;
     RECT  5.404 26.544 5.537 31.944 ;
     RECT  5.404 10.32 5.609 19.608 ;
     RECT  5.609 10.656 5.789 19.608 ;
     RECT  5.404 2.256 6.329 7.176 ;
     RECT  5.404 23.088 6.433 24.936 ;
     RECT  6.433 23.088 6.476 25.176 ;
     RECT  5.404 8.448 6.505 9.336 ;
     RECT  6.476 22.992 6.577 25.176 ;
     RECT  6.517 21.984 6.613 22.008 ;
     RECT  6.577 22.992 6.649 25.224 ;
     RECT  6.329 2.304 6.653 7.176 ;
     RECT  5.789 10.656 6.689 18.792 ;
     RECT  6.613 21.12 6.829 22.008 ;
     RECT  6.649 22.992 6.829 25.272 ;
     RECT  6.653 4.464 6.949 7.176 ;
     RECT  6.505 8.304 6.949 9.336 ;
     RECT  6.689 10.656 6.949 12.888 ;
     RECT  6.829 21.12 7.045 25.272 ;
     RECT  6.689 13.92 7.153 18.792 ;
     RECT  7.045 20.4 7.225 25.272 ;
     RECT  7.153 13.92 7.261 18.84 ;
     RECT  6.653 2.304 7.621 3.336 ;
     RECT  5.537 26.544 7.669 31.752 ;
     RECT  7.225 20.064 7.765 25.272 ;
     RECT  7.621 2.304 7.808 3.432 ;
     RECT  6.949 4.464 7.808 9.432 ;
     RECT  6.949 10.464 7.808 12.888 ;
     RECT  7.261 13.92 7.808 19.08 ;
     RECT  7.765 20.064 7.808 25.56 ;
     RECT  7.669 26.544 7.808 31.944 ;
     RECT  7.808 2.148 7.912 32.412 ;
     RECT  7.912 2.4 7.949 32.142 ;
     RECT  7.949 2.418 8.104 32.142 ;
     RECT  8.104 2.88 8.129 25.56 ;
     RECT  8.129 2.88 8.243 4.68 ;
     RECT  8.129 5.712 8.381 25.56 ;
     RECT  8.243 2.88 8.705 4.584 ;
     RECT  8.381 5.712 8.777 20.424 ;
     RECT  8.777 7.152 9.137 20.424 ;
     RECT  8.381 21.648 9.245 25.56 ;
     RECT  9.245 22.752 9.353 25.56 ;
     RECT  9.245 21.648 9.385 21.672 ;
     RECT  9.137 7.152 9.484 15.192 ;
     RECT  8.104 26.544 9.529 31.752 ;
     RECT  9.353 25.536 9.565 25.56 ;
     RECT  9.529 26.544 9.565 31.848 ;
     RECT  8.777 5.712 9.637 6.12 ;
     RECT  8.705 2.88 10.429 3.96 ;
     RECT  9.484 9.792 10.429 15.192 ;
     RECT  9.137 16.272 10.429 20.424 ;
     RECT  9.385 21.504 10.465 21.672 ;
     RECT  9.353 22.752 10.465 24.504 ;
     RECT  10.429 2.88 10.508 4.488 ;
     RECT  9.637 5.568 10.508 6.12 ;
     RECT  9.484 7.152 10.508 8.424 ;
     RECT  10.429 9.792 10.508 20.424 ;
     RECT  10.465 21.504 10.508 24.504 ;
     RECT  9.565 25.536 10.508 31.848 ;
     RECT  10.508 2.148 10.612 32.412 ;
     RECT  10.612 2.418 10.804 32.142 ;
     RECT  10.804 24.144 10.901 27.72 ;
     RECT  10.804 17.472 11.081 22.776 ;
     RECT  10.804 8.448 11.585 16.392 ;
     RECT  10.804 28.752 11.837 31.752 ;
     RECT  11.081 17.472 11.905 19.8 ;
     RECT  10.804 3.024 11.941 7.176 ;
     RECT  11.585 10.176 11.941 16.392 ;
     RECT  11.905 17.424 11.941 19.8 ;
     RECT  11.081 21.072 12.044 22.776 ;
     RECT  10.901 24.144 12.044 24.744 ;
     RECT  10.901 25.872 12.044 27.72 ;
     RECT  11.837 28.752 12.044 30.648 ;
     RECT  11.941 10.176 12.049 19.8 ;
     RECT  12.044 21.072 12.131 24.744 ;
     RECT  12.131 23.952 12.172 24.744 ;
     RECT  11.941 2.784 12.193 7.176 ;
     RECT  12.049 10.176 12.229 19.896 ;
     RECT  12.131 21.072 12.229 22.344 ;
     RECT  11.837 31.68 12.229 31.752 ;
     RECT  12.172 24 12.445 24.744 ;
     RECT  12.044 25.872 12.445 30.648 ;
     RECT  12.193 2.784 12.517 7.368 ;
     RECT  11.585 8.448 12.517 9.096 ;
     RECT  12.877 0.576 12.961 0.6 ;
     RECT  12.517 2.784 13.208 9.096 ;
     RECT  12.229 10.176 13.208 22.344 ;
     RECT  12.445 24 13.208 30.648 ;
     RECT  12.229 31.68 13.208 31.848 ;
     RECT  13.208 2.148 13.312 32.412 ;
     RECT  13.312 2.418 13.504 32.142 ;
     RECT  13.504 2.496 13.709 7.176 ;
     RECT  13.504 26.592 13.709 31.752 ;
     RECT  13.504 8.208 13.745 21.672 ;
     RECT  13.709 30.816 13.781 31.752 ;
     RECT  13.709 2.496 13.997 4.776 ;
     RECT  13.709 5.856 14.141 7.176 ;
     RECT  13.745 8.208 14.213 10.92 ;
     RECT  13.709 26.592 14.249 29.592 ;
     RECT  13.997 2.784 14.321 4.776 ;
     RECT  13.745 12.096 14.321 21.672 ;
     RECT  13.781 30.912 14.465 31.752 ;
     RECT  14.249 26.736 14.501 29.592 ;
     RECT  14.141 6 14.533 7.176 ;
     RECT  14.213 8.208 14.533 10.632 ;
     RECT  14.465 31.248 14.605 31.752 ;
     RECT  14.501 26.736 14.609 28.248 ;
     RECT  14.321 2.88 14.893 4.776 ;
     RECT  13.504 23.52 14.897 25.608 ;
     RECT  14.897 23.52 14.933 25.272 ;
     RECT  14.893 2.88 15.217 4.968 ;
     RECT  14.533 6 15.217 10.632 ;
     RECT  14.321 12.096 15.289 21.528 ;
     RECT  15.217 2.88 15.325 10.632 ;
     RECT  14.609 26.736 15.433 28.008 ;
     RECT  14.501 29.472 15.433 29.592 ;
     RECT  14.605 31.248 15.433 31.896 ;
     RECT  15.325 2.832 15.469 10.632 ;
     RECT  15.469 2.832 15.541 10.824 ;
     RECT  15.289 12.096 15.541 21.72 ;
     RECT  15.541 2.832 15.613 21.72 ;
     RECT  15.613 2.784 15.793 21.72 ;
     RECT  15.793 2.592 15.908 21.72 ;
     RECT  14.933 23.52 15.908 24.408 ;
     RECT  15.433 26.592 15.908 28.008 ;
     RECT  15.433 29.472 15.908 31.896 ;
     RECT  15.908 2.148 16.012 32.412 ;
     RECT  16.012 2.418 16.204 32.142 ;
     RECT  16.204 27.936 16.265 31.704 ;
     RECT  16.204 22.704 16.553 23.928 ;
     RECT  16.553 22.704 16.733 22.776 ;
     RECT  16.204 2.592 17.129 19.416 ;
     RECT  16.204 25.344 17.269 26.856 ;
     RECT  16.204 20.832 17.417 21.72 ;
     RECT  16.265 27.936 17.485 31.464 ;
     RECT  16.733 22.752 17.557 22.776 ;
     RECT  17.129 2.592 17.881 18.84 ;
     RECT  17.485 27.888 17.953 31.464 ;
     RECT  17.809 20.4 18.025 20.424 ;
     RECT  17.881 2.544 18.241 18.84 ;
     RECT  17.557 22.752 18.241 22.824 ;
     RECT  16.553 23.856 18.241 23.928 ;
     RECT  18.241 22.752 18.493 23.928 ;
     RECT  17.269 25.2 18.493 26.856 ;
     RECT  17.953 27.888 18.493 31.944 ;
     RECT  18.241 2.544 18.529 18.984 ;
     RECT  18.529 2.544 18.608 19.032 ;
     RECT  18.025 20.112 18.608 20.424 ;
     RECT  17.417 21.696 18.608 21.72 ;
     RECT  18.493 22.752 18.608 31.944 ;
     RECT  18.608 2.148 18.712 32.412 ;
     RECT  18.712 2.148 18.904 32.142 ;
     RECT  18.904 7.92 19.001 19.032 ;
     RECT  18.313 1.104 19.141 1.128 ;
     RECT  18.904 2.148 19.141 6.888 ;
     RECT  19.141 1.104 19.357 6.888 ;
     RECT  19.357 0.816 19.429 6.888 ;
     RECT  18.904 20.496 19.897 21.288 ;
     RECT  18.904 31.92 19.897 32.04 ;
     RECT  19.429 0.72 19.933 6.888 ;
     RECT  19.001 7.92 19.933 7.944 ;
     RECT  19.897 31.824 19.933 32.04 ;
     RECT  19.933 0.72 19.969 7.944 ;
     RECT  18.904 23.088 19.969 30.696 ;
     RECT  19.933 31.824 19.969 32.136 ;
     RECT  19.969 0.72 20.077 8.04 ;
     RECT  20.077 0.72 20.149 8.232 ;
     RECT  19.001 9.264 20.149 19.032 ;
     RECT  19.897 20.112 20.185 21.288 ;
     RECT  20.185 20.016 20.365 21.288 ;
     RECT  20.149 0.72 20.473 19.032 ;
     RECT  20.365 20.016 20.473 21.384 ;
     RECT  19.969 23.088 20.509 32.136 ;
     RECT  20.509 22.8 21.449 32.136 ;
     RECT  20.473 0.72 21.564 21.384 ;
     RECT  21.449 22.992 21.564 32.136 ;
    LAYER M5 ;
     RECT  12.816 0.016 12.936 0.611 ;
     RECT  12.816 0.611 12.84 2.137 ;
     RECT  2.4 2.137 2.52 2.151 ;
     RECT  5.1 2.137 5.22 2.151 ;
     RECT  7.8 2.137 7.92 2.151 ;
     RECT  10.5 2.137 10.62 2.151 ;
     RECT  12.816 2.137 13.32 2.151 ;
     RECT  15.9 2.137 16.02 2.151 ;
     RECT  18.6 2.137 18.72 2.151 ;
     RECT  0.144 2.245 0.168 2.771 ;
     RECT  2.4 2.151 2.712 2.821 ;
     RECT  0.24 2.773 0.264 3.109 ;
     RECT  0.24 3.109 0.312 3.205 ;
     RECT  2.4 2.821 3.432 3.347 ;
     RECT  7.8 2.151 8.112 3.397 ;
     RECT  0.24 3.205 0.36 3.589 ;
     RECT  5.1 2.151 5.412 3.925 ;
     RECT  0.24 3.589 0.408 4.019 ;
     RECT  0.24 4.019 0.36 4.115 ;
     RECT  0.24 4.115 0.312 4.645 ;
     RECT  2.4 3.347 2.856 4.691 ;
     RECT  7.8 3.397 8.232 4.691 ;
     RECT  4.56 3.925 5.412 5.027 ;
     RECT  12.816 2.151 13.512 5.077 ;
     RECT  2.4 4.691 2.808 5.269 ;
     RECT  0.192 4.645 0.312 5.317 ;
     RECT  9.408 3.925 9.432 5.557 ;
     RECT  10.5 2.151 10.812 5.557 ;
     RECT  12.24 5.077 13.512 5.699 ;
     RECT  2.304 5.269 2.808 5.701 ;
     RECT  7.8 4.691 8.112 5.989 ;
     RECT  9.408 5.557 10.812 5.989 ;
     RECT  0.192 5.317 0.36 6.085 ;
     RECT  9.216 5.989 10.812 6.131 ;
     RECT  14.688 6.325 14.712 6.659 ;
     RECT  0.144 6.085 0.36 6.709 ;
     RECT  0.144 6.709 0.552 6.899 ;
     RECT  0.144 6.899 0.264 7.139 ;
     RECT  2.304 5.701 3 7.141 ;
     RECT  7.44 5.989 8.112 7.381 ;
     RECT  9.216 6.131 9.432 8.435 ;
     RECT  5.1 5.027 5.412 8.437 ;
     RECT  0.24 7.139 0.264 8.579 ;
     RECT  2.304 7.141 3.432 8.627 ;
     RECT  2.304 8.627 2.808 8.675 ;
     RECT  2.304 8.675 2.712 8.771 ;
     RECT  9.264 8.435 9.432 8.963 ;
     RECT  4.464 8.437 5.412 11.173 ;
     RECT  6.96 7.381 8.112 11.173 ;
     RECT  9.264 8.963 9.288 11.173 ;
     RECT  3.84 11.173 5.412 11.509 ;
     RECT  6.96 11.173 9.288 11.509 ;
     RECT  0.24 11.701 0.264 11.845 ;
     RECT  2.4 8.771 2.712 11.941 ;
     RECT  3.84 11.509 9.288 11.941 ;
     RECT  15.9 2.151 16.212 12.373 ;
     RECT  2.4 11.941 9.288 12.563 ;
     RECT  2.4 12.563 6.168 13.139 ;
     RECT  0.144 11.845 0.264 13.477 ;
     RECT  2.4 13.139 5.412 13.621 ;
     RECT  0.144 13.477 0.312 14.291 ;
     RECT  10.5 6.131 10.812 14.725 ;
     RECT  7.8 12.563 9.288 14.773 ;
     RECT  2.304 13.621 5.412 15.443 ;
     RECT  6.864 14.773 9.288 16.019 ;
     RECT  0.144 14.291 0.264 16.307 ;
     RECT  7.8 16.019 9.288 16.307 ;
     RECT  10.5 14.725 11.112 16.403 ;
     RECT  10.5 16.403 10.812 16.501 ;
     RECT  2.4 15.443 5.412 16.885 ;
     RECT  15.12 12.373 16.212 17.077 ;
     RECT  2.4 16.885 5.832 17.125 ;
     RECT  15.12 17.077 17.064 17.171 ;
     RECT  2.304 17.125 5.832 17.317 ;
     RECT  15.9 17.171 17.064 17.411 ;
     RECT  12.816 5.699 13.512 17.509 ;
     RECT  0.144 16.307 0.168 17.603 ;
     RECT  2.304 17.317 6.072 17.891 ;
     RECT  7.8 16.307 8.712 18.181 ;
     RECT  12 17.509 13.512 18.275 ;
     RECT  7.392 18.181 8.712 18.325 ;
     RECT  9.888 16.501 10.812 18.325 ;
     RECT  2.304 17.891 5.832 18.467 ;
     RECT  7.392 18.325 10.812 18.803 ;
     RECT  10.5 18.803 10.812 19.333 ;
     RECT  12 18.275 12.024 19.333 ;
     RECT  2.304 18.467 5.412 19.427 ;
     RECT  0.288 17.605 0.312 19.571 ;
     RECT  2.304 19.427 4.056 19.763 ;
     RECT  10.5 19.333 12.024 19.813 ;
     RECT  2.304 19.763 2.712 20.003 ;
     RECT  3.84 19.763 4.056 20.003 ;
     RECT  7.392 18.803 9.096 20.147 ;
     RECT  10.5 19.813 12.168 21.253 ;
     RECT  13.2 18.275 13.512 21.253 ;
     RECT  2.4 20.003 2.712 21.733 ;
     RECT  4.032 20.003 4.056 21.827 ;
     RECT  2.4 21.733 2.808 22.163 ;
     RECT  7.8 20.147 9.096 22.259 ;
     RECT  10.5 21.253 13.512 22.355 ;
     RECT  5.1 19.427 5.412 23.173 ;
     RECT  0.144 23.125 0.168 23.315 ;
     RECT  0.288 23.653 0.312 23.891 ;
     RECT  4.512 23.173 5.412 23.939 ;
     RECT  6.528 21.973 6.552 23.987 ;
     RECT  7.8 22.259 8.76 23.987 ;
     RECT  10.5 22.355 12.12 23.987 ;
     RECT  10.5 23.987 11.688 24.755 ;
     RECT  13.2 22.355 13.512 25.525 ;
     RECT  3.984 24.661 4.008 25.717 ;
     RECT  3.888 25.717 4.008 25.763 ;
     RECT  10.5 24.755 11.544 26.725 ;
     RECT  13.2 25.525 13.608 26.771 ;
     RECT  2.4 22.163 2.712 27.157 ;
     RECT  2.4 27.157 2.808 27.205 ;
     RECT  3.888 25.763 3.912 27.205 ;
     RECT  7.8 23.987 8.112 27.349 ;
     RECT  0.144 26.581 0.168 27.877 ;
     RECT  5.1 23.939 5.412 28.117 ;
     RECT  6.864 27.349 8.112 28.211 ;
     RECT  0.144 27.877 0.312 28.309 ;
     RECT  2.4 27.205 3.912 28.453 ;
     RECT  10.5 26.725 12.12 28.453 ;
     RECT  13.2 26.771 13.512 28.453 ;
     RECT  13.2 28.453 13.608 28.933 ;
     RECT  2.4 28.453 3.96 29.029 ;
     RECT  5.1 28.117 5.544 29.029 ;
     RECT  2.4 29.029 5.544 29.269 ;
     RECT  9.744 28.453 12.12 29.555 ;
     RECT  2.304 29.269 5.544 29.603 ;
     RECT  0.144 28.309 0.552 29.699 ;
     RECT  9.744 29.555 11.544 30.227 ;
     RECT  2.304 29.603 5.412 30.467 ;
     RECT  10.5 30.227 11.544 30.611 ;
     RECT  7.8 28.211 8.112 30.613 ;
     RECT  0.24 29.699 0.552 30.661 ;
     RECT  10.5 30.611 10.92 30.707 ;
     RECT  2.304 30.467 3.528 30.803 ;
     RECT  0.24 30.661 0.84 30.805 ;
     RECT  13.2 28.933 13.656 30.851 ;
     RECT  2.4 30.803 3.336 31.427 ;
     RECT  4.512 30.467 5.412 31.619 ;
     RECT  13.2 30.851 13.608 31.667 ;
     RECT  2.4 31.427 2.856 31.955 ;
     RECT  7.68 30.613 8.112 31.955 ;
     RECT  2.4 31.955 2.712 32.409 ;
     RECT  5.1 31.619 5.412 32.409 ;
     RECT  7.8 31.955 8.112 32.409 ;
     RECT  10.5 30.707 10.812 32.409 ;
     RECT  13.2 31.667 13.512 32.409 ;
     RECT  15.9 17.411 16.212 32.409 ;
     RECT  18.6 2.151 18.912 32.409 ;
     RECT  2.4 32.409 2.52 32.423 ;
     RECT  5.1 32.409 5.22 32.423 ;
     RECT  7.8 32.409 7.92 32.423 ;
     RECT  10.5 32.409 10.62 32.423 ;
     RECT  13.2 32.409 13.32 32.423 ;
     RECT  15.9 32.409 16.02 32.423 ;
     RECT  18.6 32.409 18.72 32.423 ;
     RECT  0.144 30.805 0.84 32.435 ;
     RECT  0.144 32.435 0.6 32.723 ;
     RECT  0.144 32.723 0.552 32.819 ;
     RECT  0.192 32.819 0.552 32.915 ;
     RECT  0.24 32.915 0.552 33.299 ;
     RECT  0.24 33.299 0.312 33.491 ;
     RECT  0.288 33.491 0.312 33.587 ;
     RECT  12.84 0.611 12.936 2.137 ;
     RECT  8.232 3.925 9.408 4.691 ;
     RECT  9.432 3.925 10.5 5.557 ;
     RECT  0.312 4.115 0.36 5.317 ;
     RECT  2.808 4.691 2.856 5.701 ;
     RECT  8.112 4.691 9.408 5.989 ;
     RECT  10.812 5.077 12.24 5.699 ;
     RECT  8.112 5.989 9.216 8.435 ;
     RECT  9.432 6.131 10.5 8.963 ;
     RECT  13.512 6.325 14.688 6.659 ;
     RECT  14.712 6.325 15.9 6.659 ;
     RECT  8.112 8.435 9.264 11.173 ;
     RECT  3.432 8.437 4.464 8.627 ;
     RECT  9.288 8.963 10.5 16.307 ;
     RECT  2.712 11.173 3.84 11.941 ;
     RECT  5.412 14.773 6.864 16.019 ;
     RECT  5.412 16.019 6.072 16.885 ;
     RECT  8.712 16.307 10.5 16.501 ;
     RECT  10.812 16.403 11.112 17.509 ;
     RECT  8.712 16.501 9.888 18.325 ;
     RECT  5.832 16.885 6.072 17.317 ;
     RECT  10.812 17.509 12 19.333 ;
     RECT  12.024 18.275 13.2 19.813 ;
     RECT  9.096 18.803 10.5 22.259 ;
     RECT  4.056 19.427 5.1 21.827 ;
     RECT  2.712 19.763 3.84 20.003 ;
     RECT  12.168 19.813 13.2 21.253 ;
     RECT  2.712 20.003 4.032 21.733 ;
     RECT  2.808 21.733 4.032 21.827 ;
     RECT  4.512 21.827 5.1 23.173 ;
     RECT  5.412 21.973 6.528 23.987 ;
     RECT  6.552 21.973 7.8 23.987 ;
     RECT  12.12 22.355 13.2 23.987 ;
     RECT  4.512 23.939 5.1 24.661 ;
     RECT  11.688 23.987 13.2 24.755 ;
     RECT  2.712 24.661 3.984 25.717 ;
     RECT  4.008 24.661 5.1 25.763 ;
     RECT  2.712 25.717 3.888 27.157 ;
     RECT  3.912 25.763 5.1 28.453 ;
     RECT  12.12 26.725 13.2 29.555 ;
     RECT  2.808 27.157 3.888 27.205 ;
     RECT  5.412 27.349 6.864 28.117 ;
     RECT  5.544 28.117 6.864 28.211 ;
     RECT  3.96 28.453 5.1 29.029 ;
     RECT  0.144 29.699 0.24 30.805 ;
     RECT  3.528 30.467 4.512 30.803 ;
     RECT  0.84 30.661 2.304 30.803 ;
     RECT  3.336 30.803 4.512 31.427 ;
  END
END hbfd_rly_304_WE
END LIBRARY
